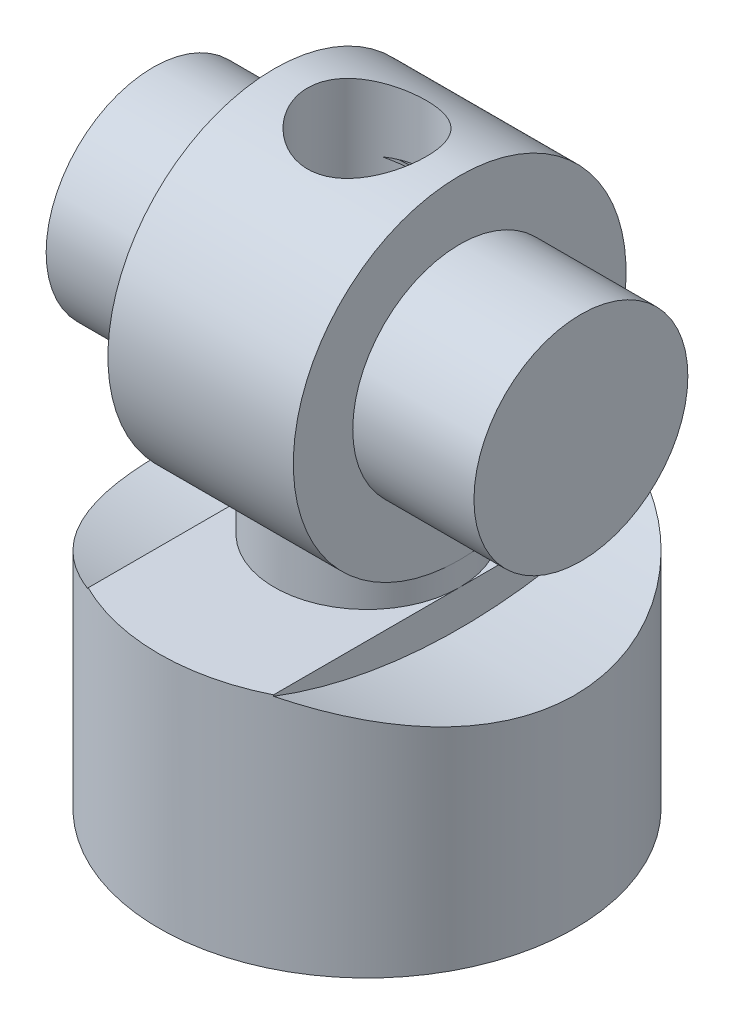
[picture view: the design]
ISO-10303-21;
HEADER;
FILE_DESCRIPTION(('STEP AP214'),'2;1');
FILE_NAME('part.step','',(''),(''),'','','');
FILE_SCHEMA(('AUTOMOTIVE_DESIGN { 1 0 10303 214 1 1 1 1 }'));
ENDSEC;
DATA;
#1=APPLICATION_CONTEXT('core data for automotive mechanical design processes');
#2=APPLICATION_PROTOCOL_DEFINITION('international standard','automotive_design',2000,#1);
#3=PRODUCT_CONTEXT('',#1,'mechanical');
#4=PRODUCT('Part','Part','',(#3));
#5=PRODUCT_RELATED_PRODUCT_CATEGORY('part','',(#4));
#6=PRODUCT_DEFINITION_FORMATION('','',#4);
#7=PRODUCT_DEFINITION_CONTEXT('part definition',#1,'design');
#8=PRODUCT_DEFINITION('design','',#6,#7);
#9=PRODUCT_DEFINITION_SHAPE('','',#8);
#10=(LENGTH_UNIT() NAMED_UNIT(*) SI_UNIT(.MILLI.,.METRE.));
#11=(NAMED_UNIT(*) PLANE_ANGLE_UNIT() SI_UNIT($,.RADIAN.));
#12=(NAMED_UNIT(*) SI_UNIT($,.STERADIAN.) SOLID_ANGLE_UNIT());
#13=UNCERTAINTY_MEASURE_WITH_UNIT(LENGTH_MEASURE(1.E-05),#10,'distance_accuracy_value','');
#14=(GEOMETRIC_REPRESENTATION_CONTEXT(3) GLOBAL_UNCERTAINTY_ASSIGNED_CONTEXT((#13)) GLOBAL_UNIT_ASSIGNED_CONTEXT((#10,
#11,#12)) REPRESENTATION_CONTEXT('',''));
#15=CARTESIAN_POINT('',(0.,0.,0.));
#16=DIRECTION('',(0.,0.,1.));
#17=DIRECTION('',(1.,0.,0.));
#18=AXIS2_PLACEMENT_3D('',#15,#16,#17);
#19=CARTESIAN_POINT('',(3.9,0.,0.));
#20=DIRECTION('',(1.,0.,0.));
#21=DIRECTION('',(0.,0.,-1.));
#22=AXIS2_PLACEMENT_3D('',#19,#20,#21);
#23=CYLINDRICAL_SURFACE('',#22,7.);
#24=CARTESIAN_POINT('',(-3.9,-7.,0.));
#25=CARTESIAN_POINT('',(-3.90000031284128,-7.0000002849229,0.101146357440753));
#26=CARTESIAN_POINT('',(-3.89606076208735,-6.99780299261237,0.202288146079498));
#27=CARTESIAN_POINT('',(-3.8803553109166,-6.98907110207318,0.4038084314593));
#28=CARTESIAN_POINT('',(-3.86858664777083,-6.98253497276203,0.504186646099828));
#29=CARTESIAN_POINT('',(-3.83737541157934,-6.96529106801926,0.70335165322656));
#30=CARTESIAN_POINT('',(-3.81793498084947,-6.95458445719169,0.802138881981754));
#31=CARTESIAN_POINT('',(-3.77162646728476,-6.92927102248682,0.997460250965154));
#32=CARTESIAN_POINT('',(-3.74475533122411,-6.91466259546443,1.09399344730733));
#33=CARTESIAN_POINT('',(-3.65367488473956,-6.8656158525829,1.37844239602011));
#34=CARTESIAN_POINT('',(-3.57884423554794,-6.82586770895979,1.56217036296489));
#35=CARTESIAN_POINT('',(-3.40371798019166,-6.73570207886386,1.91400928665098));
#36=CARTESIAN_POINT('',(-3.30341621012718,-6.68528201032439,2.08211644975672));
#37=CARTESIAN_POINT('',(-3.07231715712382,-6.57405157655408,2.41123481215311));
#38=CARTESIAN_POINT('',(-2.93988015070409,-6.51276165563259,2.57093203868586));
#39=CARTESIAN_POINT('',(-2.65187991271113,-6.38792749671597,2.86710248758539));
#40=CARTESIAN_POINT('',(-2.4962931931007,-6.32438101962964,3.00355181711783));
#41=CARTESIAN_POINT('',(-2.14756313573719,-6.19461051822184,3.26342871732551));
#42=CARTESIAN_POINT('',(-1.9522073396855,-6.12877524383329,3.38410558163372));
#43=CARTESIAN_POINT('',(-1.54017690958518,-6.01028349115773,3.59036592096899));
#44=CARTESIAN_POINT('',(-1.32353352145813,-5.95760808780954,3.67599990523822));
#45=CARTESIAN_POINT('',(-0.922013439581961,-5.88301311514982,3.79393677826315));
#46=CARTESIAN_POINT('',(-0.740093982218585,-5.85694711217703,3.83368428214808));
#47=CARTESIAN_POINT('',(-0.370897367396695,-5.82184998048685,3.88678839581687));
#48=CARTESIAN_POINT('',(-0.183625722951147,-5.81280192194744,3.9001712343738));
#49=CARTESIAN_POINT('',(0.191083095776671,-5.81303377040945,3.89982520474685));
#50=CARTESIAN_POINT('',(0.37852022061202,-5.8223342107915,3.8860659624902));
#51=CARTESIAN_POINT('',(0.747931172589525,-5.85794372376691,3.83216617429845));
#52=CARTESIAN_POINT('',(0.92990134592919,-5.88426391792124,3.79200837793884));
#53=CARTESIAN_POINT('',(1.28390008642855,-5.95046957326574,3.68723511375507));
#54=CARTESIAN_POINT('',(1.45593022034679,-5.99035288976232,3.62262351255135));
#55=CARTESIAN_POINT('',(1.78727171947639,-6.07937613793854,3.47115130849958));
#56=CARTESIAN_POINT('',(1.94657809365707,-6.12851967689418,3.3842820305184));
#57=CARTESIAN_POINT('',(2.2737904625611,-6.23962592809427,3.17538598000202));
#58=CARTESIAN_POINT('',(2.43929114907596,-6.30240002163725,3.05001538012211));
#59=CARTESIAN_POINT('',(2.74839589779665,-6.4283539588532,2.77475098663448));
#60=CARTESIAN_POINT('',(2.89198236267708,-6.49153408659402,2.62483768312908));
#61=CARTESIAN_POINT('',(3.16801707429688,-6.61889865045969,2.28605157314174));
#62=CARTESIAN_POINT('',(3.29781181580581,-6.68252127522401,2.09475977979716));
#63=CARTESIAN_POINT('',(3.46646074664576,-6.76786771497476,1.79084562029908));
#64=CARTESIAN_POINT('',(3.51835131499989,-6.79464354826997,1.68666859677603));
#65=CARTESIAN_POINT('',(3.612893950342,-6.84407556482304,1.47329042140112));
#66=CARTESIAN_POINT('',(3.65555155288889,-6.8667342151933,1.36409232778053));
#67=CARTESIAN_POINT('',(3.72840544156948,-6.90580423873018,1.14932095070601));
#68=CARTESIAN_POINT('',(3.75926673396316,-6.92254271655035,1.04403213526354));
#69=CARTESIAN_POINT('',(3.81209300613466,-6.95137123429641,0.830670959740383));
#70=CARTESIAN_POINT('',(3.83406268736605,-6.96346373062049,0.722600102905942));
#71=CARTESIAN_POINT('',(3.868792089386,-6.9826458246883,0.504603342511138));
#72=CARTESIAN_POINT('',(3.88155641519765,-6.9897379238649,0.394678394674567));
#73=CARTESIAN_POINT('',(3.89769038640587,-6.99871019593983,0.173933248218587));
#74=CARTESIAN_POINT('',(3.90106096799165,-7.00059088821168,0.0631131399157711));
#75=CARTESIAN_POINT('',(3.89851220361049,-6.9991712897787,-0.145684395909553));
#76=CARTESIAN_POINT('',(3.8936119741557,-6.99643934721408,-0.243680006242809));
#77=CARTESIAN_POINT('',(3.87646786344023,-6.98691292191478,-0.438858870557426));
#78=CARTESIAN_POINT('',(3.86422167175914,-6.98011716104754,-0.536041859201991));
#79=CARTESIAN_POINT('',(3.8325365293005,-6.96262599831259,-0.728834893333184));
#80=CARTESIAN_POINT('',(3.81310029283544,-6.95193206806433,-0.824445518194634));
#81=CARTESIAN_POINT('',(3.7672642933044,-6.92689811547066,-1.01350789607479));
#82=CARTESIAN_POINT('',(3.7408618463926,-6.91255668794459,-1.10695880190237));
#83=CARTESIAN_POINT('',(3.65188020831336,-6.86467000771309,-1.38231185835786));
#84=CARTESIAN_POINT('',(3.5793522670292,-6.82616282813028,-1.56025439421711));
#85=CARTESIAN_POINT('',(3.41035528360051,-6.73908732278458,-1.90153537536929));
#86=CARTESIAN_POINT('',(3.31387989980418,-6.69051633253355,-2.06486993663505));
#87=CARTESIAN_POINT('',(3.0884274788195,-6.58161394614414,-2.39055758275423));
#88=CARTESIAN_POINT('',(2.95712331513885,-6.52058610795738,-2.5510686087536));
#89=CARTESIAN_POINT('',(2.67130243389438,-6.39603792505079,-2.8490076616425));
#90=CARTESIAN_POINT('',(2.51676008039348,-6.33251488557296,-2.98640983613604));
#91=CARTESIAN_POINT('',(2.17019140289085,-6.20252665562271,-3.24840604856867));
#92=CARTESIAN_POINT('',(1.97595074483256,-6.13642030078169,-3.37027211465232));
#93=CARTESIAN_POINT('',(1.5660225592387,-6.0169979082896,-3.57914696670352));
#94=CARTESIAN_POINT('',(1.35036576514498,-5.96366390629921,-3.66620482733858));
#95=CARTESIAN_POINT('',(0.949863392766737,-5.88745193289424,-3.78707116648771));
#96=CARTESIAN_POINT('',(0.767997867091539,-5.86053840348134,-3.82820584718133));
#97=CARTESIAN_POINT('',(0.398636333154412,-5.82368322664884,-3.88405483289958));
#98=CARTESIAN_POINT('',(0.211146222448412,-5.81372439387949,-3.89879589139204));
#99=CARTESIAN_POINT('',(-0.16431738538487,-5.81220321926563,-3.90106353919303));
#100=CARTESIAN_POINT('',(-0.352291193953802,-5.82066508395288,-3.88855431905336));
#101=CARTESIAN_POINT('',(-0.722985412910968,-5.85478864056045,-3.83697351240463));
#102=CARTESIAN_POINT('',(-0.905702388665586,-5.88046132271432,-3.79788495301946));
#103=CARTESIAN_POINT('',(-1.26056326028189,-5.94547234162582,-3.69526481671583));
#104=CARTESIAN_POINT('',(-1.43274964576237,-5.98475081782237,-3.63184018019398));
#105=CARTESIAN_POINT('',(-1.76456240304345,-6.07272836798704,-3.48273610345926));
#106=CARTESIAN_POINT('',(-1.92418392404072,-6.12143105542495,-3.39704812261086));
#107=CARTESIAN_POINT('',(-2.25197054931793,-6.23169761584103,-3.1908552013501));
#108=CARTESIAN_POINT('',(-2.41778139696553,-6.29409283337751,-3.06704558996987));
#109=CARTESIAN_POINT('',(-2.72777488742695,-6.41955139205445,-2.79497203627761));
#110=CARTESIAN_POINT('',(-2.87193982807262,-6.48261523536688,-2.64668828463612));
#111=CARTESIAN_POINT('',(-3.14998913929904,-6.61026335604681,-2.31081364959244));
#112=CARTESIAN_POINT('',(-3.28116085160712,-6.67429932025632,-2.12072173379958));
#113=CARTESIAN_POINT('',(-3.45204991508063,-6.76049282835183,-1.81846116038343));
#114=CARTESIAN_POINT('',(-3.50471596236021,-6.787588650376,-1.71481303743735));
#115=CARTESIAN_POINT('',(-3.60086999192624,-6.83773159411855,-1.5024293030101));
#116=CARTESIAN_POINT('',(-3.64436349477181,-6.86078114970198,-1.39369680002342));
#117=CARTESIAN_POINT('',(-3.71848344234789,-6.90045090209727,-1.18090483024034));
#118=CARTESIAN_POINT('',(-3.74986495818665,-6.91743981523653,-1.07717625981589));
#119=CARTESIAN_POINT('',(-3.80397740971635,-6.94692221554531,-0.866908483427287));
#120=CARTESIAN_POINT('',(-3.8267128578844,-6.95941804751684,-0.760370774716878));
#121=CARTESIAN_POINT('',(-3.86321922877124,-6.97955808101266,-0.545364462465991));
#122=CARTESIAN_POINT('',(-3.87699416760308,-6.98720445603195,-0.436896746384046));
#123=CARTESIAN_POINT('',(-3.89538409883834,-6.99742510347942,-0.218950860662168));
#124=CARTESIAN_POINT('',(-3.89999966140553,-6.99999969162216,-0.109472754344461));
#125=CARTESIAN_POINT('',(-3.9,-7.,0.));
#126=B_SPLINE_CURVE_WITH_KNOTS('',3,(#24,#25,#26,#27,#28,#29,#30,#31,#32,#33,#34,#35,#36,#37,
#38,#39,#40,#41,#42,#43,#44,#45,#46,#47,#48,#49,#50,#51,#52,#53,#54,#55,#56,#57,#58,#59,#60,#61,
#62,#63,#64,#65,#66,#67,#68,#69,#70,#71,#72,#73,#74,#75,#76,#77,#78,#79,#80,#81,#82,#83,#84,#85,
#86,#87,#88,#89,#90,#91,#92,#93,#94,#95,#96,#97,#98,#99,#100,#101,#102,#103,#104,#105,#106,#107,
#108,#109,#110,#111,#112,#113,#114,#115,#116,#117,#118,#119,#120,#121,#122,#123,#124,#125),
.UNSPECIFIED.,.T.,.F.,(4,2,2,2,2,2,2,2,2,2,2,2,2,2,2,2,2,2,2,2,2,2,2,2,2,2,2,2,2,2,2,2,2,2,2,2,
2,2,2,2,2,2,2,2,2,2,2,2,2,2,4),(0.,0.303330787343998,0.606768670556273,0.910121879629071,
1.21359992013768,1.81765602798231,2.42185845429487,3.06822728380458,3.71525645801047,
4.42832801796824,5.14036813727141,5.70199096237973,6.26305477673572,6.82474682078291,
7.38680627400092,7.94877689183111,8.51096687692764,9.15905767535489,9.80766618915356,
10.5228095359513,10.8806537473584,11.2382828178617,11.5707819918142,11.903105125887,
12.2352618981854,12.5673855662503,12.8614963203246,13.1556996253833,13.4497919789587,
13.7439978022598,14.3292696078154,14.9146965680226,15.5605601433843,16.2071415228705,
16.9195476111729,17.6309457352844,18.1936677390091,18.7558190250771,19.3187094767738,
19.8819597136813,20.4427626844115,21.0037811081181,21.6495812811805,22.2959067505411,
23.0107914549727,23.3684940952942,23.7259808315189,24.0546214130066,24.383090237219,
24.7114117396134,25.0397128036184),.UNSPECIFIED.);
#127=CARTESIAN_POINT('',(3.9,-7.,0.));
#128=VERTEX_POINT('',#127);
#129=CARTESIAN_POINT('',(-3.9,-7.,0.));
#130=VERTEX_POINT('',#129);
#131=EDGE_CURVE('E174',#128,#130,#126,.T.);
#132=ORIENTED_EDGE('',*,*,#131,.T.);
#133=CARTESIAN_POINT('',(-3.9,0.,0.));
#134=DIRECTION('',(1.,0.,0.));
#135=DIRECTION('',(0.,0.,-1.));
#136=AXIS2_PLACEMENT_3D('',#133,#134,#135);
#137=CIRCLE('',#136,7.);
#138=EDGE_CURVE('E290',#130,#130,#137,.T.);
#139=ORIENTED_EDGE('',*,*,#138,.T.);
#140=EDGE_CURVE('E299',#130,#128,#126,.T.);
#141=ORIENTED_EDGE('',*,*,#140,.T.);
#142=CARTESIAN_POINT('',(3.9,0.,0.));
#143=DIRECTION('',(1.,0.,0.));
#144=DIRECTION('',(0.,0.,-1.));
#145=AXIS2_PLACEMENT_3D('',#142,#143,#144);
#146=CIRCLE('',#145,7.);
#147=EDGE_CURVE('E293',#128,#128,#146,.T.);
#148=ORIENTED_EDGE('',*,*,#147,.F.);
#149=EDGE_LOOP('',(#132,#139,#141,#148));
#150=FACE_BOUND('',#149,.T.);
#151=CARTESIAN_POINT('',(-2.5,7.,0.));
#152=CARTESIAN_POINT('',(-2.49999223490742,6.99999423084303,-0.13564073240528));
#153=CARTESIAN_POINT('',(-2.48890866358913,6.99601508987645,-0.271414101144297));
#154=CARTESIAN_POINT('',(-2.44496507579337,6.98050486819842,-0.539073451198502));
#155=CARTESIAN_POINT('',(-2.41207047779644,6.96896179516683,-0.67095291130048));
#156=CARTESIAN_POINT('',(-2.32580712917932,6.93957817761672,-0.926706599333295));
#157=CARTESIAN_POINT('',(-2.27248899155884,6.92175320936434,-1.05059973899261));
#158=CARTESIAN_POINT('',(-2.14708821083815,6.88160372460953,-1.28763407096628));
#159=CARTESIAN_POINT('',(-2.07500711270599,6.85927957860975,-1.40077614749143));
#160=CARTESIAN_POINT('',(-1.91115888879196,6.81147433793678,-1.61758480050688));
#161=CARTESIAN_POINT('',(-1.81878583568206,6.78590953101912,-1.72077491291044));
#162=CARTESIAN_POINT('',(-1.6182590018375,6.73493649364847,-1.91057783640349));
#163=CARTESIAN_POINT('',(-1.51010025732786,6.70952831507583,-1.99718541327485));
#164=CARTESIAN_POINT('',(-1.276602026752,6.66080066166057,-2.15423743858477));
#165=CARTESIAN_POINT('',(-1.15080488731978,6.63758100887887,-2.22403549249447));
#166=CARTESIAN_POINT('',(-0.888295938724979,6.59714347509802,-2.34127586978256));
#167=CARTESIAN_POINT('',(-0.751588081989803,6.57992343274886,-2.3887262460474));
#168=CARTESIAN_POINT('',(-0.476577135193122,6.55432037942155,-2.45809130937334));
#169=CARTESIAN_POINT('',(-0.338530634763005,6.54562733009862,-2.4809052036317));
#170=CARTESIAN_POINT('',(-0.0603163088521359,6.53715061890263,-2.50316152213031));
#171=CARTESIAN_POINT('',(0.0798507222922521,6.53736369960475,-2.50261249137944));
#172=CARTESIAN_POINT('',(0.350355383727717,6.54640587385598,-2.47885081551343));
#173=CARTESIAN_POINT('',(0.480817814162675,6.55477360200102,-2.45685171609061));
#174=CARTESIAN_POINT('',(0.736061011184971,6.57842075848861,-2.39280867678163));
#175=CARTESIAN_POINT('',(0.860840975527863,6.59370115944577,-2.35076191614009));
#176=CARTESIAN_POINT('',(1.10377675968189,6.62975215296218,-2.24709441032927));
#177=CARTESIAN_POINT('',(1.22177540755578,6.65061550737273,-2.18513901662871));
#178=CARTESIAN_POINT('',(1.44606164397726,6.69544587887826,-2.04364869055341));
#179=CARTESIAN_POINT('',(1.55234602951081,6.71941374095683,-1.96410896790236));
#180=CARTESIAN_POINT('',(1.75694257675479,6.7695208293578,-1.7840468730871));
#181=CARTESIAN_POINT('',(1.85438627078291,6.79570379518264,-1.68254775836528));
#182=CARTESIAN_POINT('',(2.03114616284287,6.84604690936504,-1.46429791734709));
#183=CARTESIAN_POINT('',(2.11045421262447,6.87020614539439,-1.34754037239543));
#184=CARTESIAN_POINT('',(2.24953773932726,6.91418824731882,-1.10000408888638));
#185=CARTESIAN_POINT('',(2.30903444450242,6.93394802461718,-0.969057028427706));
#186=CARTESIAN_POINT('',(2.40477778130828,6.96641261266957,-0.698268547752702));
#187=CARTESIAN_POINT('',(2.44107169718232,6.97913176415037,-0.558445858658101));
#188=CARTESIAN_POINT('',(2.47668095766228,6.99169887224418,-0.347747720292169));
#189=CARTESIAN_POINT('',(2.48541369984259,6.99480177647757,-0.278535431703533));
#190=CARTESIAN_POINT('',(2.49707521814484,6.99895382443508,-0.139560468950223));
#191=CARTESIAN_POINT('',(2.50000399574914,7.00000296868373,-0.0697977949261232));
#192=CARTESIAN_POINT('',(2.49999223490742,6.99999423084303,0.135640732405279));
#193=CARTESIAN_POINT('',(2.48890866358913,6.99601508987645,0.271414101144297));
#194=CARTESIAN_POINT('',(2.44496507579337,6.98050486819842,0.539073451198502));
#195=CARTESIAN_POINT('',(2.41207047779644,6.96896179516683,0.67095291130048));
#196=CARTESIAN_POINT('',(2.32580712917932,6.93957817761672,0.926706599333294));
#197=CARTESIAN_POINT('',(2.27248899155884,6.92175320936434,1.05059973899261));
#198=CARTESIAN_POINT('',(2.14708821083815,6.88160372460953,1.28763407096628));
#199=CARTESIAN_POINT('',(2.07500711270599,6.85927957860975,1.40077614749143));
#200=CARTESIAN_POINT('',(1.91115888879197,6.81147433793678,1.61758480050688));
#201=CARTESIAN_POINT('',(1.81878583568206,6.78590953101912,1.72077491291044));
#202=CARTESIAN_POINT('',(1.6182590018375,6.73493649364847,1.91057783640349));
#203=CARTESIAN_POINT('',(1.51010025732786,6.70952831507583,1.99718541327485));
#204=CARTESIAN_POINT('',(1.276602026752,6.66080066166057,2.15423743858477));
#205=CARTESIAN_POINT('',(1.15080488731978,6.63758100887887,2.22403549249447));
#206=CARTESIAN_POINT('',(0.88829593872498,6.59714347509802,2.34127586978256));
#207=CARTESIAN_POINT('',(0.751588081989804,6.57992343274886,2.3887262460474));
#208=CARTESIAN_POINT('',(0.476577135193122,6.55432037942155,2.45809130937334));
#209=CARTESIAN_POINT('',(0.338530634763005,6.54562733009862,2.4809052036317));
#210=CARTESIAN_POINT('',(0.060316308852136,6.53715061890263,2.50316152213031));
#211=CARTESIAN_POINT('',(-0.0798507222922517,6.53736369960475,2.50261249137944));
#212=CARTESIAN_POINT('',(-0.350355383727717,6.54640587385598,2.47885081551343));
#213=CARTESIAN_POINT('',(-0.480817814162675,6.55477360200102,2.45685171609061));
#214=CARTESIAN_POINT('',(-0.736061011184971,6.57842075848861,2.39280867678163));
#215=CARTESIAN_POINT('',(-0.860840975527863,6.59370115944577,2.35076191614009));
#216=CARTESIAN_POINT('',(-1.10377675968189,6.62975215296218,2.24709441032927));
#217=CARTESIAN_POINT('',(-1.22177540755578,6.65061550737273,2.18513901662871));
#218=CARTESIAN_POINT('',(-1.44606164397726,6.69544587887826,2.04364869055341));
#219=CARTESIAN_POINT('',(-1.55234602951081,6.71941374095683,1.96410896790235));
#220=CARTESIAN_POINT('',(-1.75694257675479,6.7695208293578,1.7840468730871));
#221=CARTESIAN_POINT('',(-1.85438627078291,6.79570379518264,1.68254775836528));
#222=CARTESIAN_POINT('',(-2.03114616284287,6.84604690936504,1.46429791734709));
#223=CARTESIAN_POINT('',(-2.11045421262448,6.87020614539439,1.34754037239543));
#224=CARTESIAN_POINT('',(-2.24953773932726,6.91418824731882,1.10000408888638));
#225=CARTESIAN_POINT('',(-2.30903444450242,6.93394802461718,0.969057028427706));
#226=CARTESIAN_POINT('',(-2.40477778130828,6.96641261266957,0.698268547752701));
#227=CARTESIAN_POINT('',(-2.44107169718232,6.97913176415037,0.5584458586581));
#228=CARTESIAN_POINT('',(-2.47668095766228,6.99169887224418,0.347747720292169));
#229=CARTESIAN_POINT('',(-2.48541369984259,6.99480177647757,0.278535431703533));
#230=CARTESIAN_POINT('',(-2.49707521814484,6.99895382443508,0.139560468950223));
#231=CARTESIAN_POINT('',(-2.50000399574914,7.00000296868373,0.0697977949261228));
#232=CARTESIAN_POINT('',(-2.5,7.,0.));
#233=B_SPLINE_CURVE_WITH_KNOTS('',3,(#151,#152,#153,#154,#155,#156,#157,#158,#159,#160,#161,
#162,#163,#164,#165,#166,#167,#168,#169,#170,#171,#172,#173,#174,#175,#176,#177,#178,#179,#180,
#181,#182,#183,#184,#185,#186,#187,#188,#189,#190,#191,#192,#193,#194,#195,#196,#197,#198,#199,
#200,#201,#202,#203,#204,#205,#206,#207,#208,#209,#210,#211,#212,#213,#214,#215,#216,#217,#218,
#219,#220,#221,#222,#223,#224,#225,#226,#227,#228,#229,#230,#231,#232),.UNSPECIFIED.,.T.,.F.,(4,
2,2,2,2,2,2,2,2,2,2,2,2,2,2,2,2,2,2,2,2,2,2,2,2,2,2,2,2,2,2,2,2,2,2,2,2,2,2,2,4),(0.,
0.406652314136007,0.8139509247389,1.22024664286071,1.62650891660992,2.0471353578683,
2.46789435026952,2.90289671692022,3.3377422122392,3.75611572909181,4.17433622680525,
4.57019166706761,4.96610282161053,5.36905142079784,5.77210992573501,6.1994977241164,
6.62707716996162,7.06044132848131,7.4929195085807,7.70217407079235,7.91142857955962,
8.31808089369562,8.72537950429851,9.13167522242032,9.53793749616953,9.95856393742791,
10.3793229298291,10.8143252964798,11.2491707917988,11.6675443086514,12.0857648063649,
12.4816202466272,12.8775314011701,13.2804800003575,13.6835385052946,14.110926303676,
14.5385057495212,14.9718699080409,15.4043480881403,15.613602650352,15.8228571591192),.UNSPECIFIED.);
#234=CARTESIAN_POINT('',(-2.5,7.,0.));
#235=VERTEX_POINT('',#234);
#236=EDGE_CURVE('E180',#235,#235,#233,.T.);
#237=ORIENTED_EDGE('',*,*,#236,.T.);
#238=EDGE_LOOP('',(#237));
#239=FACE_BOUND('',#238,.T.);
#240=ADVANCED_FACE('F14',(#150,#239),#23,.T.);
#241=CARTESIAN_POINT('',(9.,0.,0.));
#242=DIRECTION('',(-1.,0.,0.));
#243=DIRECTION('',(0.,0.,1.));
#244=AXIS2_PLACEMENT_3D('',#241,#242,#243);
#245=CYLINDRICAL_SURFACE('',#244,4.5);
#246=CARTESIAN_POINT('',(0.,-3.74165738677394,2.5));
#247=CARTESIAN_POINT('',(0.127867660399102,-3.7416726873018,2.4999886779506));
#248=CARTESIAN_POINT('',(0.255847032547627,-3.74831704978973,2.49012046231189));
#249=CARTESIAN_POINT('',(0.507679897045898,-3.77384839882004,2.45123834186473));
#250=CARTESIAN_POINT('',(0.631526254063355,-3.79275551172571,2.42219296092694));
#251=CARTESIAN_POINT('',(0.870945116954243,-3.83989933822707,2.34672518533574));
#252=CARTESIAN_POINT('',(0.986564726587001,-3.86807667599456,2.30041313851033));
#253=CARTESIAN_POINT('',(1.20834600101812,-3.93048941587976,2.19206578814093));
#254=CARTESIAN_POINT('',(1.31450555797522,-3.96472616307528,2.13002699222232));
#255=CARTESIAN_POINT('',(1.52641671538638,-4.03969403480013,1.98449846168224));
#256=CARTESIAN_POINT('',(1.63099357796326,-4.08073069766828,1.89945493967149));
#257=CARTESIAN_POINT('',(1.82534633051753,-4.16222299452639,1.71353751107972));
#258=CARTESIAN_POINT('',(1.91511315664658,-4.20267825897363,1.61265398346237));
#259=CARTESIAN_POINT('',(2.08508983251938,-4.28269640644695,1.3870985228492));
#260=CARTESIAN_POINT('',(2.1637603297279,-4.32186646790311,1.26111369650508));
#261=CARTESIAN_POINT('',(2.29824166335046,-4.39073714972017,0.995108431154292));
#262=CARTESIAN_POINT('',(2.35407027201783,-4.4204451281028,0.85509901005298));
#263=CARTESIAN_POINT('',(2.43630568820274,-4.46480622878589,0.577542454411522));
#264=CARTESIAN_POINT('',(2.46480060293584,-4.48051966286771,0.440787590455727));
#265=CARTESIAN_POINT('',(2.49853448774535,-4.49916269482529,0.163616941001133));
#266=CARTESIAN_POINT('',(2.50379152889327,-4.50210222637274,0.0232040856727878));
#267=CARTESIAN_POINT('',(2.4914765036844,-4.4952695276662,-0.241178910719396));
#268=CARTESIAN_POINT('',(2.47628215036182,-4.48682112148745,-0.365303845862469));
#269=CARTESIAN_POINT('',(2.42789099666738,-4.46029652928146,-0.608906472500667));
#270=CARTESIAN_POINT('',(2.39469280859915,-4.44221960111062,-0.72838380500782));
#271=CARTESIAN_POINT('',(2.31126649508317,-4.39780601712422,-0.960979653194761));
#272=CARTESIAN_POINT('',(2.26086630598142,-4.37138611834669,-1.07401990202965));
#273=CARTESIAN_POINT('',(2.14483738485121,-4.31251997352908,-1.29025059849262));
#274=CARTESIAN_POINT('',(2.07920386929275,-4.28007183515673,-1.39343793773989));
#275=CARTESIAN_POINT('',(1.92640653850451,-4.20785286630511,-1.59909620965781));
#276=CARTESIAN_POINT('',(1.83767397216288,-4.16766932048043,-1.70025747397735));
#277=CARTESIAN_POINT('',(1.64533173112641,-4.08650106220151,-1.88703556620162));
#278=CARTESIAN_POINT('',(1.54170632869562,-4.04551554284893,-1.97263574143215));
#279=CARTESIAN_POINT('',(1.31107929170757,-3.96312397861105,-2.13367090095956));
#280=CARTESIAN_POINT('',(1.1828097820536,-3.92201714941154,-2.2074790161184));
#281=CARTESIAN_POINT('',(0.980669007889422,-3.86749177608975,-2.30082855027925));
#282=CARTESIAN_POINT('',(0.911652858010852,-3.8505034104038,-2.32905476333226));
#283=CARTESIAN_POINT('',(0.770776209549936,-3.81960529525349,-2.3793879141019));
#284=CARTESIAN_POINT('',(0.698917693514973,-3.80569344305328,-2.4014990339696));
#285=CARTESIAN_POINT('',(0.558744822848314,-3.7825660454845,-2.43774893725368));
#286=CARTESIAN_POINT('',(0.49060568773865,-3.77306418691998,-2.45238335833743));
#287=CARTESIAN_POINT('',(0.352979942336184,-3.75764870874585,-2.47593920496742));
#288=CARTESIAN_POINT('',(0.283494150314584,-3.75173297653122,-2.48486399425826));
#289=CARTESIAN_POINT('',(0.143844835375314,-3.7437735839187,-2.49684067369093));
#290=CARTESIAN_POINT('',(0.0736818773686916,-3.74172693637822,-2.49989709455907));
#291=CARTESIAN_POINT('',(-0.0666321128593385,-3.74159115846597,-2.5000979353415));
#292=CARTESIAN_POINT('',(-0.136783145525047,-3.74350157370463,-2.49724303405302));
#293=CARTESIAN_POINT('',(-0.32521266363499,-3.75390669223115,-2.48160454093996));
#294=CARTESIAN_POINT('',(-0.442885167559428,-3.7660681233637,-2.46327912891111));
#295=CARTESIAN_POINT('',(-0.673061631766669,-3.79999671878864,-2.41059641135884));
#296=CARTESIAN_POINT('',(-0.785563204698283,-3.8217682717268,-2.37623178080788));
#297=CARTESIAN_POINT('',(-1.00774180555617,-3.8734200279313,-2.29111009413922));
#298=CARTESIAN_POINT('',(-1.11711092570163,-3.90359765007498,-2.23973536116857));
#299=CARTESIAN_POINT('',(-1.32632576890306,-3.96852930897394,-2.12255957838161));
#300=CARTESIAN_POINT('',(-1.42616680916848,-4.00328557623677,-2.05675148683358));
#301=CARTESIAN_POINT('',(-1.63049062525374,-4.08021308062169,-1.90016864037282));
#302=CARTESIAN_POINT('',(-1.73309682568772,-4.12267224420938,-1.80707526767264));
#303=CARTESIAN_POINT('',(-1.92199935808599,-4.20557655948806,-1.60470900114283));
#304=CARTESIAN_POINT('',(-2.00828561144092,-4.24602045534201,-1.49542618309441));
#305=CARTESIAN_POINT('',(-2.16643294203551,-4.32300875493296,-1.25626042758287));
#306=CARTESIAN_POINT('',(-2.23726807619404,-4.3592262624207,-1.12558547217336));
#307=CARTESIAN_POINT('',(-2.35519631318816,-4.42090637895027,-0.851602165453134));
#308=CARTESIAN_POINT('',(-2.40231447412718,-4.44638033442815,-0.708307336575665));
#309=CARTESIAN_POINT('',(-2.46664777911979,-4.48148519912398,-0.428990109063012));
#310=CARTESIAN_POINT('',(-2.48643742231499,-4.49247473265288,-0.29373267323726));
#311=CARTESIAN_POINT('',(-2.50362240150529,-4.5020067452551,-0.0213910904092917));
#312=CARTESIAN_POINT('',(-2.50103007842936,-4.50055608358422,0.115692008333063));
#313=CARTESIAN_POINT('',(-2.47491437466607,-4.4861017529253,0.374337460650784));
#314=CARTESIAN_POINT('',(-2.45334235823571,-4.47417531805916,0.49616574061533));
#315=CARTESIAN_POINT('',(-2.39292228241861,-4.44133257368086,0.734167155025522));
#316=CARTESIAN_POINT('',(-2.3540722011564,-4.42041521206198,0.8503396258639));
#317=CARTESIAN_POINT('',(-2.25905612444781,-4.3705432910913,1.07814775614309));
#318=CARTESIAN_POINT('',(-2.202363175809,-4.34134725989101,1.18950897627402));
#319=CARTESIAN_POINT('',(-2.07393542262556,-4.27762772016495,1.40148896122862));
#320=CARTESIAN_POINT('',(-2.00219469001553,-4.24310211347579,1.50210346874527));
#321=CARTESIAN_POINT('',(-1.83613517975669,-4.16717195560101,1.70217916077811));
#322=CARTESIAN_POINT('',(-1.74016022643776,-4.12543450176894,1.8001424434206));
#323=CARTESIAN_POINT('',(-1.53330418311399,-4.04252541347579,1.97933250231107));
#324=CARTESIAN_POINT('',(-1.42240466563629,-4.0013545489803,2.06053826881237));
#325=CARTESIAN_POINT('',(-1.17899936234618,-3.92122408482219,2.20944802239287));
#326=CARTESIAN_POINT('',(-1.04552040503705,-3.88262653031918,2.27579178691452));
#327=CARTESIAN_POINT('',(-0.836526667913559,-3.83343009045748,2.35707752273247));
#328=CARTESIAN_POINT('',(-0.765460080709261,-3.81848976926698,2.38112244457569));
#329=CARTESIAN_POINT('',(-0.620861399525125,-3.79215325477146,2.4228459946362));
#330=CARTESIAN_POINT('',(-0.547330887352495,-3.78075483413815,2.44052862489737));
#331=CARTESIAN_POINT('',(-0.395409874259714,-3.7617084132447,2.4697920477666));
#332=CARTESIAN_POINT('',(-0.316943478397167,-3.75423236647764,2.48109451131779));
#333=CARTESIAN_POINT('',(-0.158999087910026,-3.74420222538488,2.49620181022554));
#334=CARTESIAN_POINT('',(-0.0795211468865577,-3.74164787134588,2.50000704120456));
#335=CARTESIAN_POINT('',(0.,-3.74165738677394,2.5));
#336=B_SPLINE_CURVE_WITH_KNOTS('',3,(#246,#247,#248,#249,#250,#251,#252,#253,#254,#255,#256,
#257,#258,#259,#260,#261,#262,#263,#264,#265,#266,#267,#268,#269,#270,#271,#272,#273,#274,#275,
#276,#277,#278,#279,#280,#281,#282,#283,#284,#285,#286,#287,#288,#289,#290,#291,#292,#293,#294,
#295,#296,#297,#298,#299,#300,#301,#302,#303,#304,#305,#306,#307,#308,#309,#310,#311,#312,#313,
#314,#315,#316,#317,#318,#319,#320,#321,#322,#323,#324,#325,#326,#327,#328,#329,#330,#331,#332,
#333,#334,#335),.UNSPECIFIED.,.T.,.F.,(4,2,2,2,2,2,2,2,2,2,2,2,2,2,2,2,2,2,2,2,2,2,2,2,2,2,2,2,
2,2,2,2,2,2,2,2,2,2,2,2,2,2,2,2,4),(0.,0.383275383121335,0.767181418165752,1.14867490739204,
1.53025318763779,1.95124472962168,2.37249297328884,2.8308639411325,3.2888775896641,
3.70817544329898,4.12714717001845,4.50138183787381,4.8756453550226,5.25376784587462,
5.63200923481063,6.05157027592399,6.47157769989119,6.92969119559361,7.15882945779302,
7.38781062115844,7.59850621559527,7.80907756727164,8.01948627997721,8.22987083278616,
8.58719279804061,8.94467811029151,9.31690871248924,9.68932132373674,10.122176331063,
10.5552977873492,11.0117233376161,11.4676656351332,11.8767730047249,12.2856548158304,
12.6568475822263,13.0280837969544,13.4115163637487,13.7951002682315,14.2233400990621,
14.6521136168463,15.1111969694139,15.3403711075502,15.5694008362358,15.80777312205,
16.0461328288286),.UNSPECIFIED.);
#337=CARTESIAN_POINT('',(0.,-3.74165738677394,2.5));
#338=VERTEX_POINT('',#337);
#339=EDGE_CURVE('E214',#338,#338,#336,.T.);
#340=ORIENTED_EDGE('',*,*,#339,.T.);
#341=EDGE_LOOP('',(#340));
#342=FACE_BOUND('',#341,.T.);
#343=CARTESIAN_POINT('',(0.,-3.30870065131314,-3.05));
#344=CARTESIAN_POINT('',(0.0740543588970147,-3.30870135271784,-3.04999955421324));
#345=CARTESIAN_POINT('',(0.148113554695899,-3.31120079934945,-3.04729547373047));
#346=CARTESIAN_POINT('',(0.29550128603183,-3.32105327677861,-3.03655247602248));
#347=CARTESIAN_POINT('',(0.368829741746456,-3.32840683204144,-3.02851298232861));
#348=CARTESIAN_POINT('',(0.586950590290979,-3.35728100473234,-2.99658701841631));
#349=CARTESIAN_POINT('',(0.729787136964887,-3.385614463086,-2.96489335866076));
#350=CARTESIAN_POINT('',(1.00481607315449,-3.45535402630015,-2.88328172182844));
#351=CARTESIAN_POINT('',(1.13710040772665,-3.49662694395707,-2.83354864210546));
#352=CARTESIAN_POINT('',(1.39123632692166,-3.58733287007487,-2.71780374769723));
#353=CARTESIAN_POINT('',(1.51308617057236,-3.6367672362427,-2.65178922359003));
#354=CARTESIAN_POINT('',(1.76446479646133,-3.74781440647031,-2.49293203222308));
#355=CARTESIAN_POINT('',(1.89204410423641,-3.81010328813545,-2.39747643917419));
#356=CARTESIAN_POINT('',(2.13108358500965,-3.93428541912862,-2.18776550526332));
#357=CARTESIAN_POINT('',(2.24252540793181,-3.99617814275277,-2.07348907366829));
#358=CARTESIAN_POINT('',(2.46301512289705,-4.1236708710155,-1.80832137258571));
#359=CARTESIAN_POINT('',(2.56913328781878,-4.18840811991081,-1.65450535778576));
#360=CARTESIAN_POINT('',(2.70696690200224,-4.27480018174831,-1.40843177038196));
#361=CARTESIAN_POINT('',(2.74934801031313,-4.30180769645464,-1.3238668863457));
#362=CARTESIAN_POINT('',(2.82644155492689,-4.35148238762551,-1.15011183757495));
#363=CARTESIAN_POINT('',(2.86115705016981,-4.37415129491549,-1.06092353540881));
#364=CARTESIAN_POINT('',(2.93723315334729,-4.42421178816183,-0.834029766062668));
#365=CARTESIAN_POINT('',(2.97356864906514,-4.44850916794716,-0.693888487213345));
#366=CARTESIAN_POINT('',(3.02602447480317,-4.48374237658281,-0.408328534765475));
#367=CARTESIAN_POINT('',(3.04216027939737,-4.49468843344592,-0.262913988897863));
#368=CARTESIAN_POINT('',(3.05336718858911,-4.5022807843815,0.0293654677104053));
#369=CARTESIAN_POINT('',(3.04840293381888,-4.49890307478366,0.176232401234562));
#370=CARTESIAN_POINT('',(3.01761506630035,-4.47809945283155,0.466749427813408));
#371=CARTESIAN_POINT('',(2.99178532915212,-4.46066941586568,0.610398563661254));
#372=CARTESIAN_POINT('',(2.92131598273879,-4.41371882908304,0.888013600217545));
#373=CARTESIAN_POINT('',(2.87702540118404,-4.38442289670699,1.02210773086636));
#374=CARTESIAN_POINT('',(2.77159197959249,-4.31597239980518,1.28074304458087));
#375=CARTESIAN_POINT('',(2.71044594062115,-4.27681596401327,1.40528240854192));
#376=CARTESIAN_POINT('',(2.56551457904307,-4.18638203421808,1.65649516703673));
#377=CARTESIAN_POINT('',(2.47995424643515,-4.13423576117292,1.78182668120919));
#378=CARTESIAN_POINT('',(2.29260341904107,-4.02464324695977,2.01721180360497));
#379=CARTESIAN_POINT('',(2.19079412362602,-3.96719089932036,2.12724743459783));
#380=CARTESIAN_POINT('',(1.95420691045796,-3.841187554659,2.34819750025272));
#381=CARTESIAN_POINT('',(1.81676442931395,-3.7723979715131,2.4561343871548));
#382=CARTESIAN_POINT('',(1.52359640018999,-3.64029455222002,2.64798057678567));
#383=CARTESIAN_POINT('',(1.36788117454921,-3.57697765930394,2.7319033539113));
#384=CARTESIAN_POINT('',(1.07873972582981,-3.4781328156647,2.85610629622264));
#385=CARTESIAN_POINT('',(0.948783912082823,-3.43957561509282,2.90201639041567));
#386=CARTESIAN_POINT('',(0.680934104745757,-3.37555318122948,2.97625031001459));
#387=CARTESIAN_POINT('',(0.54305511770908,-3.35006405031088,3.00460625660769));
#388=CARTESIAN_POINT('',(0.261369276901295,-3.31605166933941,3.04212029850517));
#389=CARTESIAN_POINT('',(0.117523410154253,-3.30766771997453,3.05112079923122));
#390=CARTESIAN_POINT('',(-0.169846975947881,-3.30994043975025,3.04865479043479));
#391=CARTESIAN_POINT('',(-0.313371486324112,-3.32059763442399,3.03718771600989));
#392=CARTESIAN_POINT('',(-0.579273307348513,-3.35672225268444,2.99716587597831));
#393=CARTESIAN_POINT('',(-0.702224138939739,-3.3804057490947,2.97065905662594));
#394=CARTESIAN_POINT('',(-0.941707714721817,-3.43813602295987,2.9036484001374));
#395=CARTESIAN_POINT('',(-1.05823445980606,-3.47219229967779,2.86313172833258));
#396=CARTESIAN_POINT('',(-1.33453129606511,-3.56435394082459,2.74826045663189));
#397=CARTESIAN_POINT('',(-1.49008084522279,-3.62637602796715,2.6668870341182));
#398=CARTESIAN_POINT('',(-1.78349065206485,-3.75646016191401,2.48031899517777));
#399=CARTESIAN_POINT('',(-1.9213174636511,-3.82453323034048,2.37508034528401));
#400=CARTESIAN_POINT('',(-2.17938375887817,-3.9604362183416,2.14091948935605));
#401=CARTESIAN_POINT('',(-2.29935531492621,-4.02824992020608,2.01169148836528));
#402=CARTESIAN_POINT('',(-2.51660188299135,-4.1560914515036,1.7321777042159));
#403=CARTESIAN_POINT('',(-2.61391283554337,-4.21613154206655,1.58192588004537));
#404=CARTESIAN_POINT('',(-2.7672445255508,-4.31303677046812,1.2910804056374));
#405=CARTESIAN_POINT('',(-2.82752395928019,-4.35212259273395,1.15347804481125));
#406=CARTESIAN_POINT('',(-2.92771339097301,-4.41786925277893,0.868215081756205));
#407=CARTESIAN_POINT('',(-2.96763645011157,-4.44453805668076,0.720560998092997));
#408=CARTESIAN_POINT('',(-3.02511265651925,-4.48311795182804,0.418279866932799));
#409=CARTESIAN_POINT('',(-3.04255880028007,-4.49495844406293,0.263623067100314));
#410=CARTESIAN_POINT('',(-3.05359112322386,-4.50243250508,-0.0469294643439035));
#411=CARTESIAN_POINT('',(-3.04718207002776,-4.49806931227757,-0.202824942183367));
#412=CARTESIAN_POINT('',(-3.01241336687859,-4.47459437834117,-0.498210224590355));
#413=CARTESIAN_POINT('',(-2.98584821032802,-4.45668871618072,-0.638015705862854));
#414=CARTESIAN_POINT('',(-2.91428327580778,-4.40906289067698,-0.910676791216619));
#415=CARTESIAN_POINT('',(-2.86928056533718,-4.37934084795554,-1.04353128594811));
#416=CARTESIAN_POINT('',(-2.75996758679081,-4.30849145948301,-1.30628099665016));
#417=CARTESIAN_POINT('',(-2.6947819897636,-4.26685537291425,-1.43567105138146));
#418=CARTESIAN_POINT('',(-2.54831500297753,-4.17589690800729,-1.68200981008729));
#419=CARTESIAN_POINT('',(-2.46702497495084,-4.12657040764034,-1.79895178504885));
#420=CARTESIAN_POINT('',(-2.27621742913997,-4.01518689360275,-2.03669083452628));
#421=CARTESIAN_POINT('',(-2.16426874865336,-3.95235046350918,-2.15517053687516));
#422=CARTESIAN_POINT('',(-1.92324507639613,-3.82568072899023,-2.37276837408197));
#423=CARTESIAN_POINT('',(-1.79415533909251,-3.76184660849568,-2.47186965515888));
#424=CARTESIAN_POINT('',(-1.52700320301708,-3.6422101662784,-2.64476720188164));
#425=CARTESIAN_POINT('',(-1.38971103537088,-3.58616592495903,-2.71958017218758));
#426=CARTESIAN_POINT('',(-1.10202420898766,-3.48481309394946,-2.84829695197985));
#427=CARTESIAN_POINT('',(-0.951651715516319,-3.43948680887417,-2.90223532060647));
#428=CARTESIAN_POINT('',(-0.668272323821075,-3.37324804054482,-2.97881254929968));
#429=CARTESIAN_POINT('',(-0.537042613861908,-3.34940288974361,-3.00534763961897));
#430=CARTESIAN_POINT('',(-0.337187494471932,-3.32517436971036,-3.03205239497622));
#431=CARTESIAN_POINT('',(-0.270072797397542,-3.3190214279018,-3.03877098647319));
#432=CARTESIAN_POINT('',(-0.135306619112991,-3.31078493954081,-3.04774423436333));
#433=CARTESIAN_POINT('',(-0.0676553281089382,-3.30870001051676,-3.05000040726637));
#434=CARTESIAN_POINT('',(0.,-3.30870065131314,-3.05));
#435=B_SPLINE_CURVE_WITH_KNOTS('',3,(#343,#344,#345,#346,#347,#348,#349,#350,#351,#352,#353,
#354,#355,#356,#357,#358,#359,#360,#361,#362,#363,#364,#365,#366,#367,#368,#369,#370,#371,#372,
#373,#374,#375,#376,#377,#378,#379,#380,#381,#382,#383,#384,#385,#386,#387,#388,#389,#390,#391,
#392,#393,#394,#395,#396,#397,#398,#399,#400,#401,#402,#403,#404,#405,#406,#407,#408,#409,#410,
#411,#412,#413,#414,#415,#416,#417,#418,#419,#420,#421,#422,#423,#424,#425,#426,#427,#428,#429,
#430,#431,#432,#433,#434),.UNSPECIFIED.,.T.,.F.,(4,2,2,2,2,2,2,2,2,2,2,2,2,2,2,2,2,2,2,2,2,2,2,
2,2,2,2,2,2,2,2,2,2,2,2,2,2,2,2,2,2,2,2,2,2,4),(0.,0.222074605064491,0.444173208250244,
0.888639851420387,1.32867397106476,1.76878136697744,2.28012572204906,2.79204704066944,
3.3816546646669,3.67634407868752,3.97091568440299,4.40924515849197,4.84723863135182,
5.28596638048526,5.72482295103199,6.1557338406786,6.58672656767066,7.06630172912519,
7.54643585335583,8.10749203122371,8.66823277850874,9.09600687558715,9.52299588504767,
9.95344853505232,10.3839130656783,10.7663784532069,11.1491951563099,11.7047959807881,
12.2614304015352,12.8257196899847,13.3891078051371,13.8528597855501,14.3163138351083,
14.7819661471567,15.247525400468,15.6758920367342,16.104326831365,16.5548361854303,
17.0055878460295,17.527655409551,18.0501750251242,18.5465955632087,19.0421906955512,
19.4481632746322,19.6511174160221,19.8540025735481),.UNSPECIFIED.);
#436=CARTESIAN_POINT('',(0.,-3.30870065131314,-3.05));
#437=VERTEX_POINT('',#436);
#438=EDGE_CURVE('E237',#437,#437,#435,.T.);
#439=ORIENTED_EDGE('',*,*,#438,.T.);
#440=EDGE_LOOP('',(#439));
#441=FACE_BOUND('',#440,.T.);
#442=ADVANCED_FACE('F159',(#342,#441),#245,.T.);
#443=CARTESIAN_POINT('',(0.,-18.,0.));
#444=DIRECTION('',(0.,-1.,0.));
#445=DIRECTION('',(0.,0.,-1.));
#446=AXIS2_PLACEMENT_3D('',#443,#444,#445);
#447=CYLINDRICAL_SURFACE('',#446,8.75);
#448=CARTESIAN_POINT('',(0.,-18.,0.));
#449=DIRECTION('',(0.,-1.,0.));
#450=DIRECTION('',(0.,0.,-1.));
#451=AXIS2_PLACEMENT_3D('',#448,#449,#450);
#452=CIRCLE('',#451,8.75);
#453=CARTESIAN_POINT('',(0.,-18.,-8.75));
#454=VERTEX_POINT('',#453);
#455=EDGE_CURVE('E281',#454,#454,#452,.T.);
#456=ORIENTED_EDGE('',*,*,#455,.F.);
#457=EDGE_LOOP('',(#456));
#458=FACE_BOUND('',#457,.T.);
#459=DIRECTION('',(0.,-1.,0.));
#460=VECTOR('',#459,1.);
#461=CARTESIAN_POINT('',(3.9,-18.,7.83278366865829));
#462=LINE('',#461,#460);
#463=CARTESIAN_POINT('',(3.9,-8.,7.83278366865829));
#464=VERTEX_POINT('',#463);
#465=CARTESIAN_POINT('',(3.9,-8.05467298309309,7.83278366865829));
#466=VERTEX_POINT('',#465);
#467=EDGE_CURVE('E278',#464,#466,#462,.T.);
#468=ORIENTED_EDGE('',*,*,#467,.F.);
#469=CARTESIAN_POINT('',(0.,-8.,0.));
#470=DIRECTION('',(0.,-1.,0.));
#471=DIRECTION('',(0.,0.,-1.));
#472=AXIS2_PLACEMENT_3D('',#469,#470,#471);
#473=CIRCLE('',#472,8.75);
#474=CARTESIAN_POINT('',(-3.9,-8.,7.83278366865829));
#475=VERTEX_POINT('',#474);
#476=EDGE_CURVE('E284',#464,#475,#473,.T.);
#477=ORIENTED_EDGE('',*,*,#476,.T.);
#478=DIRECTION('',(0.,-1.,0.));
#479=VECTOR('',#478,1.);
#480=CARTESIAN_POINT('',(-3.9,-18.,7.83278366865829));
#481=LINE('',#480,#479);
#482=CARTESIAN_POINT('',(-3.9,-8.05467298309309,7.83278366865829));
#483=VERTEX_POINT('',#482);
#484=EDGE_CURVE('E268',#483,#475,#481,.F.);
#485=ORIENTED_EDGE('',*,*,#484,.F.);
#486=CARTESIAN_POINT('',(-3.9,-8.05467298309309,-7.83278366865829));
#487=CARTESIAN_POINT('',(-4.12452384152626,-8.09737217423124,-7.721006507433));
#488=CARTESIAN_POINT('',(-4.34380093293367,-8.1426514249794,-7.5997666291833));
#489=CARTESIAN_POINT('',(-4.77055982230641,-8.23689755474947,-7.33939091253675));
#490=CARTESIAN_POINT('',(-4.97804428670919,-8.28586359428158,-7.20025914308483));
#491=CARTESIAN_POINT('',(-5.38011565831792,-8.38605555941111,-6.90500663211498));
#492=CARTESIAN_POINT('',(-5.57469632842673,-8.43728255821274,-6.74887776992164));
#493=CARTESIAN_POINT('',(-5.94972754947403,-8.54050248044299,-6.42069527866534));
#494=CARTESIAN_POINT('',(-6.13017736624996,-8.59249544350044,-6.24864082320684));
#495=CARTESIAN_POINT('',(-6.4758207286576,-8.69578877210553,-5.88967916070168));
#496=CARTESIAN_POINT('',(-6.64101593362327,-8.74708921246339,-5.7027735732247));
#497=CARTESIAN_POINT('',(-6.95509462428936,-8.8475918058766,-5.31520163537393));
#498=CARTESIAN_POINT('',(-7.10397859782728,-8.89679402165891,-5.11453569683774));
#499=CARTESIAN_POINT('',(-7.3843624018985,-8.99174565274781,-4.70065534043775));
#500=CARTESIAN_POINT('',(-7.51586399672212,-9.03749541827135,-4.4874421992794));
#501=CARTESIAN_POINT('',(-7.76039107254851,-9.12425375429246,-4.04988941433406));
#502=CARTESIAN_POINT('',(-7.87342610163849,-9.16526477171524,-3.82555559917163));
#503=CARTESIAN_POINT('',(-8.07907473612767,-9.24103260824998,-3.36942343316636));
#504=CARTESIAN_POINT('',(-8.17187940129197,-9.2758473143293,-3.13772094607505));
#505=CARTESIAN_POINT('',(-8.33757753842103,-9.33872146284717,-2.66640099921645));
#506=CARTESIAN_POINT('',(-8.41047104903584,-9.36678091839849,-2.42678355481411));
#507=CARTESIAN_POINT('',(-8.5355569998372,-9.41531310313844,-1.94152657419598));
#508=CARTESIAN_POINT('',(-8.58775595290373,-9.43578821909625,-1.69588895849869));
#509=CARTESIAN_POINT('',(-8.67089101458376,-9.46854701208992,-1.2005061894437));
#510=CARTESIAN_POINT('',(-8.70182846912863,-9.48083120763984,-0.950761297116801));
#511=CARTESIAN_POINT('',(-8.7407495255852,-9.49630702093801,-0.4658358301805));
#512=CARTESIAN_POINT('',(-8.750113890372,-9.50004546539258,-0.2307824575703));
#513=CARTESIAN_POINT('',(-8.7498840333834,-9.49995370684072,0.239307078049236));
#514=CARTESIAN_POINT('',(-8.7402907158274,-9.49612386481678,0.474343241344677));
#515=CARTESIAN_POINT('',(-8.70225130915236,-9.48100009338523,0.942599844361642));
#516=CARTESIAN_POINT('',(-8.67380828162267,-9.46970737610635,1.17582057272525));
#517=CARTESIAN_POINT('',(-8.59836743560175,-9.43996057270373,1.63877460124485));
#518=CARTESIAN_POINT('',(-8.55136958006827,-9.42150647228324,1.86850789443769));
#519=CARTESIAN_POINT('',(-8.44061471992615,-9.37843869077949,2.31748063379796));
#520=CARTESIAN_POINT('',(-8.37728079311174,-9.35398116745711,2.53683975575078));
#521=CARTESIAN_POINT('',(-8.23390957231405,-9.29929221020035,2.96937079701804));
#522=CARTESIAN_POINT('',(-8.153866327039,-9.26905871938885,3.18254048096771));
#523=CARTESIAN_POINT('',(-7.9777519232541,-9.20354769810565,3.60132955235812));
#524=CARTESIAN_POINT('',(-7.88168151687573,-9.16827040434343,3.80694929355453));
#525=CARTESIAN_POINT('',(-7.67419463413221,-9.09348021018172,4.2095784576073));
#526=CARTESIAN_POINT('',(-7.56277248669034,-9.05396574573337,4.40658466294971));
#527=CARTESIAN_POINT('',(-7.31951823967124,-8.96958509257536,4.80034457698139));
#528=CARTESIAN_POINT('',(-7.18695156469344,-8.92455123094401,4.99660873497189));
#529=CARTESIAN_POINT('',(-6.90662819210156,-8.83192026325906,5.37744590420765));
#530=CARTESIAN_POINT('',(-6.75886512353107,-8.78432208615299,5.5620139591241));
#531=CARTESIAN_POINT('',(-6.4491916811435,-8.68777999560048,5.91828375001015));
#532=CARTESIAN_POINT('',(-6.28729068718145,-8.63883698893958,6.08999387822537));
#533=CARTESIAN_POINT('',(-5.95018583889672,-8.54078643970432,6.4197690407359));
#534=CARTESIAN_POINT('',(-5.77497970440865,-8.4916788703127,6.5778317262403));
#535=CARTESIAN_POINT('',(-5.33439681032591,-8.37371263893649,6.94407214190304));
#536=CARTESIAN_POINT('',(-5.06252636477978,-8.30539786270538,7.14473831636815));
#537=CARTESIAN_POINT('',(-4.63830883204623,-8.20738306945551,7.42139553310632));
#538=CARTESIAN_POINT('',(-4.49422811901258,-8.17546615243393,7.50952743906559));
#539=CARTESIAN_POINT('',(-4.20090392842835,-8.11353556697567,7.67746300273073));
#540=CARTESIAN_POINT('',(-4.05166060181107,-8.08352184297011,7.7572669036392));
#541=CARTESIAN_POINT('',(-3.9,-8.0546729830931,7.83278366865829));
#542=B_SPLINE_CURVE_WITH_KNOTS('',3,(#486,#487,#488,#489,#490,#491,#492,#493,#494,#495,#496,
#497,#498,#499,#500,#501,#502,#503,#504,#505,#506,#507,#508,#509,#510,#511,#512,#513,#514,#515,
#516,#517,#518,#519,#520,#521,#522,#523,#524,#525,#526,#527,#528,#529,#530,#531,#532,#533,#534,
#535,#536,#537,#538,#539,#540,#541),.UNSPECIFIED.,.F.,.F.,(4,2,2,2,2,2,2,2,2,2,2,2,2,2,2,2,2,2,
2,2,2,2,2,2,2,2,2,4),(0.,0.762954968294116,1.5257367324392,2.28888454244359,3.0520719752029,
3.81517629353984,4.57825778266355,5.34126176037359,6.10386997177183,6.85892977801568,
7.61398811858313,8.36880864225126,9.1235813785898,9.82851622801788,10.5334174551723,
11.2382042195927,11.9429923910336,12.6310960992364,13.3194453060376,14.0077622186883,
14.6963340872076,15.4187923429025,16.14155472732,16.8638411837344,17.5862517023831,
18.6179068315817,19.1333253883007,19.6487288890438),.UNSPECIFIED.);
#543=CARTESIAN_POINT('',(-3.9,-8.05467298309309,-7.83278366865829));
#544=VERTEX_POINT('',#543);
#545=EDGE_CURVE('E123',#544,#483,#542,.T.);
#546=ORIENTED_EDGE('',*,*,#545,.F.);
#547=DIRECTION('',(0.,-1.,0.));
#548=VECTOR('',#547,1.);
#549=CARTESIAN_POINT('',(-3.9,-18.,-7.83278366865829));
#550=LINE('',#549,#548);
#551=CARTESIAN_POINT('',(-3.9,-8.,-7.83278366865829));
#552=VERTEX_POINT('',#551);
#553=EDGE_CURVE('E270',#552,#544,#550,.T.);
#554=ORIENTED_EDGE('',*,*,#553,.F.);
#555=CARTESIAN_POINT('',(3.9,-8.,-7.83278366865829));
#556=VERTEX_POINT('',#555);
#557=EDGE_CURVE('E285',#552,#556,#473,.T.);
#558=ORIENTED_EDGE('',*,*,#557,.T.);
#559=DIRECTION('',(0.,-1.,0.));
#560=VECTOR('',#559,1.);
#561=CARTESIAN_POINT('',(3.9,-18.,-7.83278366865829));
#562=LINE('',#561,#560);
#563=CARTESIAN_POINT('',(3.9,-8.05467298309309,-7.83278366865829));
#564=VERTEX_POINT('',#563);
#565=EDGE_CURVE('E276',#564,#556,#562,.F.);
#566=ORIENTED_EDGE('',*,*,#565,.F.);
#567=CARTESIAN_POINT('',(3.9,-8.05467298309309,7.83278366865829));
#568=CARTESIAN_POINT('',(4.12452384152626,-8.09737217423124,7.721006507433));
#569=CARTESIAN_POINT('',(4.34380093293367,-8.1426514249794,7.5997666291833));
#570=CARTESIAN_POINT('',(4.77055982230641,-8.23689755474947,7.33939091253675));
#571=CARTESIAN_POINT('',(4.97804428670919,-8.28586359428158,7.20025914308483));
#572=CARTESIAN_POINT('',(5.38011565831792,-8.38605555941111,6.90500663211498));
#573=CARTESIAN_POINT('',(5.57469632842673,-8.43728255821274,6.74887776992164));
#574=CARTESIAN_POINT('',(5.94972754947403,-8.54050248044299,6.42069527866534));
#575=CARTESIAN_POINT('',(6.13017736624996,-8.59249544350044,6.24864082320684));
#576=CARTESIAN_POINT('',(6.4758207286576,-8.69578877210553,5.88967916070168));
#577=CARTESIAN_POINT('',(6.64101593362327,-8.74708921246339,5.7027735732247));
#578=CARTESIAN_POINT('',(6.95509462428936,-8.8475918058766,5.31520163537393));
#579=CARTESIAN_POINT('',(7.10397859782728,-8.89679402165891,5.11453569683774));
#580=CARTESIAN_POINT('',(7.3843624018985,-8.99174565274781,4.70065534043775));
#581=CARTESIAN_POINT('',(7.51586399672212,-9.03749541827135,4.4874421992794));
#582=CARTESIAN_POINT('',(7.76039107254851,-9.12425375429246,4.04988941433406));
#583=CARTESIAN_POINT('',(7.87342610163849,-9.16526477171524,3.82555559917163));
#584=CARTESIAN_POINT('',(8.07907473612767,-9.24103260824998,3.36942343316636));
#585=CARTESIAN_POINT('',(8.17187940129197,-9.2758473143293,3.13772094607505));
#586=CARTESIAN_POINT('',(8.33757753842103,-9.33872146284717,2.66640099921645));
#587=CARTESIAN_POINT('',(8.41047104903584,-9.36678091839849,2.42678355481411));
#588=CARTESIAN_POINT('',(8.5355569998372,-9.41531310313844,1.94152657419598));
#589=CARTESIAN_POINT('',(8.58775595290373,-9.43578821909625,1.69588895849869));
#590=CARTESIAN_POINT('',(8.67089101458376,-9.46854701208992,1.2005061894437));
#591=CARTESIAN_POINT('',(8.70182846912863,-9.48083120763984,0.950761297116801));
#592=CARTESIAN_POINT('',(8.7407495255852,-9.49630702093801,0.4658358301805));
#593=CARTESIAN_POINT('',(8.750113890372,-9.50004546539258,0.2307824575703));
#594=CARTESIAN_POINT('',(8.7498840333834,-9.49995370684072,-0.239307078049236));
#595=CARTESIAN_POINT('',(8.7402907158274,-9.49612386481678,-0.474343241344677));
#596=CARTESIAN_POINT('',(8.70225130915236,-9.48100009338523,-0.942599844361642));
#597=CARTESIAN_POINT('',(8.67380828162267,-9.46970737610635,-1.17582057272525));
#598=CARTESIAN_POINT('',(8.59836743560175,-9.43996057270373,-1.63877460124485));
#599=CARTESIAN_POINT('',(8.55136958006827,-9.42150647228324,-1.86850789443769));
#600=CARTESIAN_POINT('',(8.44061471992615,-9.37843869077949,-2.31748063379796));
#601=CARTESIAN_POINT('',(8.37728079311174,-9.35398116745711,-2.53683975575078));
#602=CARTESIAN_POINT('',(8.23390957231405,-9.29929221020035,-2.96937079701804));
#603=CARTESIAN_POINT('',(8.153866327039,-9.26905871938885,-3.18254048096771));
#604=CARTESIAN_POINT('',(7.9777519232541,-9.20354769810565,-3.60132955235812));
#605=CARTESIAN_POINT('',(7.88168151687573,-9.16827040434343,-3.80694929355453));
#606=CARTESIAN_POINT('',(7.67419463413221,-9.09348021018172,-4.2095784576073));
#607=CARTESIAN_POINT('',(7.56277248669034,-9.05396574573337,-4.40658466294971));
#608=CARTESIAN_POINT('',(7.31951823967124,-8.96958509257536,-4.80034457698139));
#609=CARTESIAN_POINT('',(7.18695156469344,-8.92455123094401,-4.99660873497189));
#610=CARTESIAN_POINT('',(6.90662819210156,-8.83192026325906,-5.37744590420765));
#611=CARTESIAN_POINT('',(6.75886512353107,-8.78432208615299,-5.5620139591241));
#612=CARTESIAN_POINT('',(6.4491916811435,-8.68777999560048,-5.91828375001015));
#613=CARTESIAN_POINT('',(6.28729068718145,-8.63883698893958,-6.08999387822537));
#614=CARTESIAN_POINT('',(5.95018583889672,-8.54078643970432,-6.4197690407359));
#615=CARTESIAN_POINT('',(5.77497970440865,-8.4916788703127,-6.5778317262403));
#616=CARTESIAN_POINT('',(5.33439681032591,-8.37371263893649,-6.94407214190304));
#617=CARTESIAN_POINT('',(5.06252636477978,-8.30539786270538,-7.14473831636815));
#618=CARTESIAN_POINT('',(4.63830883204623,-8.20738306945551,-7.42139553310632));
#619=CARTESIAN_POINT('',(4.49422811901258,-8.17546615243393,-7.50952743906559));
#620=CARTESIAN_POINT('',(4.20090392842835,-8.11353556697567,-7.67746300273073));
#621=CARTESIAN_POINT('',(4.05166060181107,-8.08352184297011,-7.7572669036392));
#622=CARTESIAN_POINT('',(3.9,-8.0546729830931,-7.83278366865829));
#623=B_SPLINE_CURVE_WITH_KNOTS('',3,(#567,#568,#569,#570,#571,#572,#573,#574,#575,#576,#577,
#578,#579,#580,#581,#582,#583,#584,#585,#586,#587,#588,#589,#590,#591,#592,#593,#594,#595,#596,
#597,#598,#599,#600,#601,#602,#603,#604,#605,#606,#607,#608,#609,#610,#611,#612,#613,#614,#615,
#616,#617,#618,#619,#620,#621,#622),.UNSPECIFIED.,.F.,.F.,(4,2,2,2,2,2,2,2,2,2,2,2,2,2,2,2,2,2,
2,2,2,2,2,2,2,2,2,4),(0.,0.762954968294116,1.5257367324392,2.28888454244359,3.0520719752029,
3.81517629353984,4.57825778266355,5.34126176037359,6.10386997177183,6.85892977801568,
7.61398811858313,8.36880864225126,9.1235813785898,9.82851622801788,10.5334174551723,
11.2382042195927,11.9429923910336,12.6310960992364,13.3194453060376,14.0077622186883,
14.6963340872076,15.4187923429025,16.14155472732,16.8638411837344,17.5862517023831,
18.6179068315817,19.1333253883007,19.6487288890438),.UNSPECIFIED.);
#624=EDGE_CURVE('E114',#466,#564,#623,.T.);
#625=ORIENTED_EDGE('',*,*,#624,.F.);
#626=EDGE_LOOP('',(#468,#477,#485,#546,#554,#558,#566,#625));
#627=FACE_BOUND('',#626,.T.);
#628=ADVANCED_FACE('F130',(#458,#627),#447,.T.);
#629=CARTESIAN_POINT('',(0.,-8.,-3.9));
#630=DIRECTION('',(0.,-1.,0.));
#631=DIRECTION('',(0.,0.,-1.));
#632=AXIS2_PLACEMENT_3D('',#629,#630,#631);
#633=PLANE('',#632);
#634=DIRECTION('',(0.,0.,1.));
#635=VECTOR('',#634,1.);
#636=CARTESIAN_POINT('',(3.9,-8.,-3.9));
#637=LINE('',#636,#635);
#638=CARTESIAN_POINT('',(3.9,-8.,0.));
#639=VERTEX_POINT('',#638);
#640=EDGE_CURVE('E273',#639,#464,#637,.T.);
#641=ORIENTED_EDGE('',*,*,#640,.F.);
#642=CARTESIAN_POINT('',(0.,-8.,0.));
#643=DIRECTION('',(0.,-1.,0.));
#644=DIRECTION('',(0.,0.,-1.));
#645=AXIS2_PLACEMENT_3D('',#642,#643,#644);
#646=CIRCLE('',#645,3.9);
#647=CARTESIAN_POINT('',(-3.9,-8.,0.));
#648=VERTEX_POINT('',#647);
#649=EDGE_CURVE('E288',#639,#648,#646,.T.);
#650=ORIENTED_EDGE('',*,*,#649,.T.);
#651=DIRECTION('',(0.,0.,-1.));
#652=VECTOR('',#651,1.);
#653=CARTESIAN_POINT('',(-3.9,-8.,-3.9));
#654=LINE('',#653,#652);
#655=EDGE_CURVE('E267',#475,#648,#654,.T.);
#656=ORIENTED_EDGE('',*,*,#655,.F.);
#657=ORIENTED_EDGE('',*,*,#476,.F.);
#658=EDGE_LOOP('',(#641,#650,#656,#657));
#659=FACE_BOUND('',#658,.T.);
#660=ADVANCED_FACE('F318',(#659),#633,.F.);
#661=EDGE_CURVE('E264',#648,#552,#654,.T.);
#662=ORIENTED_EDGE('',*,*,#661,.F.);
#663=EDGE_CURVE('E35',#648,#639,#646,.T.);
#664=ORIENTED_EDGE('',*,*,#663,.T.);
#665=EDGE_CURVE('E275',#556,#639,#637,.T.);
#666=ORIENTED_EDGE('',*,*,#665,.F.);
#667=ORIENTED_EDGE('',*,*,#557,.F.);
#668=EDGE_LOOP('',(#662,#664,#666,#667));
#669=FACE_BOUND('',#668,.T.);
#670=ADVANCED_FACE('F322',(#669),#633,.F.);
#671=CARTESIAN_POINT('',(-3.9,7.,0.));
#672=DIRECTION('',(-1.,0.,0.));
#673=DIRECTION('',(0.,0.,1.));
#674=AXIS2_PLACEMENT_3D('',#671,#672,#673);
#675=PLANE('',#674);
#676=CARTESIAN_POINT('',(-3.9,0.,0.));
#677=DIRECTION('',(-1.,0.,0.));
#678=DIRECTION('',(0.,0.,1.));
#679=AXIS2_PLACEMENT_3D('',#676,#677,#678);
#680=CIRCLE('',#679,4.5);
#681=CARTESIAN_POINT('',(-3.9,0.,4.5));
#682=VERTEX_POINT('',#681);
#683=EDGE_CURVE('E505',#682,#682,#680,.F.);
#684=ORIENTED_EDGE('',*,*,#683,.T.);
#685=EDGE_LOOP('',(#684));
#686=FACE_BOUND('',#685,.T.);
#687=ORIENTED_EDGE('',*,*,#138,.F.);
#688=EDGE_LOOP('',(#687));
#689=FACE_BOUND('',#688,.T.);
#690=ADVANCED_FACE('F16',(#686,#689),#675,.T.);
#691=CARTESIAN_POINT('',(3.9,4.5,0.));
#692=DIRECTION('',(1.,0.,0.));
#693=DIRECTION('',(0.,0.,-1.));
#694=AXIS2_PLACEMENT_3D('',#691,#692,#693);
#695=PLANE('',#694);
#696=ORIENTED_EDGE('',*,*,#147,.T.);
#697=EDGE_LOOP('',(#696));
#698=FACE_BOUND('',#697,.T.);
#699=CARTESIAN_POINT('',(3.9,0.,0.));
#700=DIRECTION('',(1.,0.,0.));
#701=DIRECTION('',(0.,0.,-1.));
#702=AXIS2_PLACEMENT_3D('',#699,#700,#701);
#703=CIRCLE('',#702,4.5);
#704=CARTESIAN_POINT('',(3.9,0.,-4.5));
#705=VERTEX_POINT('',#704);
#706=EDGE_CURVE('E295',#705,#705,#703,.T.);
#707=ORIENTED_EDGE('',*,*,#706,.F.);
#708=EDGE_LOOP('',(#707));
#709=FACE_BOUND('',#708,.T.);
#710=ADVANCED_FACE('F145',(#698,#709),#695,.T.);
#711=CARTESIAN_POINT('',(0.,-18.,-8.75));
#712=DIRECTION('',(0.,1.,0.));
#713=DIRECTION('',(0.,0.,1.));
#714=AXIS2_PLACEMENT_3D('',#711,#712,#713);
#715=PLANE('',#714);
#716=CARTESIAN_POINT('',(0.,-18.,0.));
#717=DIRECTION('',(0.,-1.,0.));
#718=DIRECTION('',(0.,0.,-1.));
#719=AXIS2_PLACEMENT_3D('',#716,#717,#718);
#720=CIRCLE('',#719,3.05);
#721=CARTESIAN_POINT('',(0.,-18.,-3.05));
#722=VERTEX_POINT('',#721);
#723=EDGE_CURVE('E506',#722,#722,#720,.T.);
#724=ORIENTED_EDGE('',*,*,#723,.F.);
#725=EDGE_LOOP('',(#724));
#726=FACE_BOUND('',#725,.T.);
#727=ORIENTED_EDGE('',*,*,#455,.T.);
#728=EDGE_LOOP('',(#727));
#729=FACE_BOUND('',#728,.T.);
#730=ADVANCED_FACE('F142',(#726,#729),#715,.F.);
#731=CARTESIAN_POINT('',(0.,-18.,0.));
#732=DIRECTION('',(0.,-1.,0.));
#733=DIRECTION('',(0.,0.,-1.));
#734=AXIS2_PLACEMENT_3D('',#731,#732,#733);
#735=CYLINDRICAL_SURFACE('',#734,3.9);
#736=ORIENTED_EDGE('',*,*,#663,.F.);
#737=ORIENTED_EDGE('',*,*,#649,.F.);
#738=EDGE_LOOP('',(#736,#737));
#739=FACE_BOUND('',#738,.T.);
#740=ORIENTED_EDGE('',*,*,#131,.F.);
#741=ORIENTED_EDGE('',*,*,#140,.F.);
#742=EDGE_LOOP('',(#740,#741));
#743=FACE_BOUND('',#742,.T.);
#744=ADVANCED_FACE('F144',(#739,#743),#735,.T.);
#745=CARTESIAN_POINT('',(-3.9,9.4470989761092,0.));
#746=DIRECTION('',(-1.,0.,0.));
#747=DIRECTION('',(0.,0.,1.));
#748=AXIS2_PLACEMENT_3D('',#745,#746,#747);
#749=PLANE('',#748);
#750=ORIENTED_EDGE('',*,*,#553,.T.);
#751=CARTESIAN_POINT('',(-3.9,12.4470989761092,0.));
#752=DIRECTION('',(-1.,0.,0.));
#753=DIRECTION('',(0.,0.,1.));
#754=AXIS2_PLACEMENT_3D('',#751,#752,#753);
#755=CIRCLE('',#754,21.9470989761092);
#756=EDGE_CURVE('E239',#544,#483,#755,.T.);
#757=ORIENTED_EDGE('',*,*,#756,.T.);
#758=ORIENTED_EDGE('',*,*,#484,.T.);
#759=ORIENTED_EDGE('',*,*,#655,.T.);
#760=ORIENTED_EDGE('',*,*,#661,.T.);
#761=EDGE_LOOP('',(#750,#757,#758,#759,#760));
#762=FACE_BOUND('',#761,.T.);
#763=ADVANCED_FACE('F152',(#762),#749,.T.);
#764=CARTESIAN_POINT('',(-17.5,12.4470989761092,0.));
#765=DIRECTION('',(-1.,0.,0.));
#766=DIRECTION('',(0.,0.,1.));
#767=AXIS2_PLACEMENT_3D('',#764,#765,#766);
#768=CYLINDRICAL_SURFACE('',#767,21.9470989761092);
#769=ORIENTED_EDGE('',*,*,#756,.F.);
#770=ORIENTED_EDGE('',*,*,#545,.T.);
#771=EDGE_LOOP('',(#769,#770));
#772=FACE_BOUND('',#771,.T.);
#773=ADVANCED_FACE('F139',(#772),#768,.F.);
#774=CARTESIAN_POINT('',(-17.5,12.4470989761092,0.));
#775=DIRECTION('',(-1.,0.,0.));
#776=DIRECTION('',(0.,0.,1.));
#777=AXIS2_PLACEMENT_3D('',#774,#775,#776);
#778=CYLINDRICAL_SURFACE('',#777,21.9470989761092);
#779=CARTESIAN_POINT('',(3.9,12.4470989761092,0.));
#780=DIRECTION('',(-1.,0.,0.));
#781=DIRECTION('',(0.,0.,1.));
#782=AXIS2_PLACEMENT_3D('',#779,#780,#781);
#783=CIRCLE('',#782,21.9470989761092);
#784=EDGE_CURVE('E261',#564,#466,#783,.T.);
#785=ORIENTED_EDGE('',*,*,#784,.T.);
#786=ORIENTED_EDGE('',*,*,#624,.T.);
#787=EDGE_LOOP('',(#785,#786));
#788=FACE_BOUND('',#787,.T.);
#789=ADVANCED_FACE('F134',(#788),#778,.F.);
#790=CARTESIAN_POINT('',(3.9,-9.5,0.));
#791=DIRECTION('',(1.,0.,0.));
#792=DIRECTION('',(0.,0.,-1.));
#793=AXIS2_PLACEMENT_3D('',#790,#791,#792);
#794=PLANE('',#793);
#795=ORIENTED_EDGE('',*,*,#467,.T.);
#796=ORIENTED_EDGE('',*,*,#784,.F.);
#797=ORIENTED_EDGE('',*,*,#565,.T.);
#798=ORIENTED_EDGE('',*,*,#665,.T.);
#799=ORIENTED_EDGE('',*,*,#640,.T.);
#800=EDGE_LOOP('',(#795,#796,#797,#798,#799));
#801=FACE_BOUND('',#800,.T.);
#802=ADVANCED_FACE('F138',(#801),#794,.T.);
#803=CARTESIAN_POINT('',(0.,-18.,0.));
#804=DIRECTION('',(0.,-1.,0.));
#805=DIRECTION('',(0.,0.,-1.));
#806=AXIS2_PLACEMENT_3D('',#803,#804,#805);
#807=CYLINDRICAL_SURFACE('',#806,3.05);
#808=ORIENTED_EDGE('',*,*,#723,.T.);
#809=EDGE_LOOP('',(#808));
#810=FACE_BOUND('',#809,.T.);
#811=ORIENTED_EDGE('',*,*,#438,.F.);
#812=EDGE_LOOP('',(#811));
#813=FACE_BOUND('',#812,.T.);
#814=ADVANCED_FACE('F203',(#810,#813),#807,.F.);
#815=CARTESIAN_POINT('',(9.,0.,0.));
#816=DIRECTION('',(1.,0.,0.));
#817=DIRECTION('',(0.,0.,-1.));
#818=AXIS2_PLACEMENT_3D('',#815,#816,#817);
#819=PLANE('',#818);
#820=CARTESIAN_POINT('',(9.,0.,0.));
#821=DIRECTION('',(1.,0.,0.));
#822=DIRECTION('',(0.,0.,-1.));
#823=AXIS2_PLACEMENT_3D('',#820,#821,#822);
#824=CIRCLE('',#823,4.5);
#825=CARTESIAN_POINT('',(9.,0.,-4.5));
#826=VERTEX_POINT('',#825);
#827=EDGE_CURVE('E191',#826,#826,#824,.T.);
#828=ORIENTED_EDGE('',*,*,#827,.T.);
#829=EDGE_LOOP('',(#828));
#830=FACE_BOUND('',#829,.T.);
#831=ADVANCED_FACE('F200',(#830),#819,.T.);
#832=ORIENTED_EDGE('',*,*,#706,.T.);
#833=EDGE_LOOP('',(#832));
#834=FACE_BOUND('',#833,.T.);
#835=ORIENTED_EDGE('',*,*,#827,.F.);
#836=EDGE_LOOP('',(#835));
#837=FACE_BOUND('',#836,.T.);
#838=ADVANCED_FACE('F168',(#834,#837),#245,.T.);
#839=ORIENTED_EDGE('',*,*,#683,.F.);
#840=EDGE_LOOP('',(#839));
#841=FACE_BOUND('',#840,.T.);
#842=CARTESIAN_POINT('',(-9.,0.,0.));
#843=DIRECTION('',(1.,0.,0.));
#844=DIRECTION('',(0.,0.,-1.));
#845=AXIS2_PLACEMENT_3D('',#842,#843,#844);
#846=CIRCLE('',#845,4.5);
#847=CARTESIAN_POINT('',(-9.,0.,-4.5));
#848=VERTEX_POINT('',#847);
#849=EDGE_CURVE('E188',#848,#848,#846,.T.);
#850=ORIENTED_EDGE('',*,*,#849,.T.);
#851=EDGE_LOOP('',(#850));
#852=FACE_BOUND('',#851,.T.);
#853=ADVANCED_FACE('F206',(#841,#852),#245,.T.);
#854=CARTESIAN_POINT('',(-9.,0.,0.));
#855=DIRECTION('',(1.,0.,0.));
#856=DIRECTION('',(0.,0.,-1.));
#857=AXIS2_PLACEMENT_3D('',#854,#855,#856);
#858=PLANE('',#857);
#859=ORIENTED_EDGE('',*,*,#849,.F.);
#860=EDGE_LOOP('',(#859));
#861=FACE_BOUND('',#860,.T.);
#862=ADVANCED_FACE('F197',(#861),#858,.F.);
#863=CARTESIAN_POINT('',(0.,-5.,0.));
#864=DIRECTION('',(0.,-1.,0.));
#865=DIRECTION('',(0.,0.,-1.));
#866=AXIS2_PLACEMENT_3D('',#863,#864,#865);
#867=CYLINDRICAL_SURFACE('',#866,2.5);
#868=CARTESIAN_POINT('',(1.4142135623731,4.,2.06155281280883));
#869=CARTESIAN_POINT('',(1.30921473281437,3.96283440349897,2.1336339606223));
#870=CARTESIAN_POINT('',(1.19805601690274,3.92718409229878,2.19802650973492));
#871=CARTESIAN_POINT('',(0.964865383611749,3.86243911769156,2.30994101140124));
#872=CARTESIAN_POINT('',(0.842766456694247,3.83338934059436,2.35734864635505));
#873=CARTESIAN_POINT('',(0.589954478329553,3.78584220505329,2.432986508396));
#874=CARTESIAN_POINT('',(0.459201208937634,3.76739862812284,2.46111913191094));
#875=CARTESIAN_POINT('',(0.194154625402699,3.74438364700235,2.49600974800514));
#876=CARTESIAN_POINT('',(0.059878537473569,3.73975415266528,2.50285725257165));
#877=CARTESIAN_POINT('',(-0.194311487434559,3.74475696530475,2.49535244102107));
#878=CARTESIAN_POINT('',(-0.314321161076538,3.75301182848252,2.48304800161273));
#879=CARTESIAN_POINT('',(-0.550520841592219,3.78011178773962,2.44158888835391));
#880=CARTESIAN_POINT('',(-0.666696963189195,3.79899168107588,2.41237883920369));
#881=CARTESIAN_POINT('',(-0.893689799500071,3.84527438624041,2.33790497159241));
#882=CARTESIAN_POINT('',(-1.00441211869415,3.8727896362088,2.29242818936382));
#883=CARTESIAN_POINT('',(-1.21650308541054,3.93313533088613,2.18725214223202));
#884=CARTESIAN_POINT('',(-1.31792246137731,3.96593388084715,2.12763726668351));
#885=CARTESIAN_POINT('',(-1.4142135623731,4.,2.06155281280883));
#886=B_SPLINE_CURVE_WITH_KNOTS('',3,(#868,#869,#870,#871,#872,#873,#874,#875,#876,#877,#878,
#879,#880,#881,#882,#883,#884,#885),.UNSPECIFIED.,.F.,.F.,(4,2,2,2,2,2,2,2,4),(0.,
0.398082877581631,0.798796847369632,1.20152522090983,1.60255766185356,1.96356027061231,
2.32575211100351,2.69287059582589,3.0578506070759),.UNSPECIFIED.);
#887=CARTESIAN_POINT('',(1.4142135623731,4.,2.06155281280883));
#888=VERTEX_POINT('',#887);
#889=CARTESIAN_POINT('',(-1.4142135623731,4.,2.06155281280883));
#890=VERTEX_POINT('',#889);
#891=EDGE_CURVE('E98',#888,#890,#886,.T.);
#892=ORIENTED_EDGE('',*,*,#891,.F.);
#893=CARTESIAN_POINT('',(0.,4.,0.));
#894=DIRECTION('',(0.,-1.,0.));
#895=DIRECTION('',(0.,0.,-1.));
#896=AXIS2_PLACEMENT_3D('',#893,#894,#895);
#897=CIRCLE('',#896,2.5);
#898=EDGE_CURVE('E189',#888,#890,#897,.T.);
#899=ORIENTED_EDGE('',*,*,#898,.T.);
#900=EDGE_LOOP('',(#892,#899));
#901=FACE_BOUND('',#900,.T.);
#902=CARTESIAN_POINT('',(0.,4.,0.));
#903=DIRECTION('',(0.,-1.,0.));
#904=DIRECTION('',(0.,0.,-1.));
#905=AXIS2_PLACEMENT_3D('',#902,#903,#904);
#906=CIRCLE('',#905,2.5);
#907=CARTESIAN_POINT('',(1.41421356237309,4.,-2.06155281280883));
#908=VERTEX_POINT('',#907);
#909=CARTESIAN_POINT('',(-1.4142135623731,4.,-2.06155281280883));
#910=VERTEX_POINT('',#909);
#911=EDGE_CURVE('E9',#908,#910,#906,.F.);
#912=ORIENTED_EDGE('',*,*,#911,.F.);
#913=CARTESIAN_POINT('',(-1.41421356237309,4.,-2.06155281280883));
#914=CARTESIAN_POINT('',(-1.30921473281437,3.96283440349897,-2.1336339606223));
#915=CARTESIAN_POINT('',(-1.19805601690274,3.92718409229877,-2.19802650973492));
#916=CARTESIAN_POINT('',(-0.964865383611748,3.86243911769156,-2.30994101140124));
#917=CARTESIAN_POINT('',(-0.842766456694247,3.83338934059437,-2.35734864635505));
#918=CARTESIAN_POINT('',(-0.589954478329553,3.78584220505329,-2.432986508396));
#919=CARTESIAN_POINT('',(-0.459201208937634,3.76739862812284,-2.46111913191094));
#920=CARTESIAN_POINT('',(-0.1941546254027,3.74438364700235,-2.49600974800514));
#921=CARTESIAN_POINT('',(-0.0598785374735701,3.73975415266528,-2.50285725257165));
#922=CARTESIAN_POINT('',(0.194311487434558,3.74475696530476,-2.49535244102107));
#923=CARTESIAN_POINT('',(0.314321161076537,3.75301182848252,-2.48304800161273));
#924=CARTESIAN_POINT('',(0.550520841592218,3.78011178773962,-2.44158888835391));
#925=CARTESIAN_POINT('',(0.666696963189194,3.79899168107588,-2.41237883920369));
#926=CARTESIAN_POINT('',(0.89368979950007,3.84527438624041,-2.33790497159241));
#927=CARTESIAN_POINT('',(1.00441211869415,3.8727896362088,-2.29242818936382));
#928=CARTESIAN_POINT('',(1.21650308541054,3.93313533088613,-2.18725214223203));
#929=CARTESIAN_POINT('',(1.31792246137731,3.96593388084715,-2.12763726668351));
#930=CARTESIAN_POINT('',(1.41421356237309,4.,-2.06155281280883));
#931=B_SPLINE_CURVE_WITH_KNOTS('',3,(#913,#914,#915,#916,#917,#918,#919,#920,#921,#922,#923,
#924,#925,#926,#927,#928,#929,#930),.UNSPECIFIED.,.F.,.F.,(4,2,2,2,2,2,2,2,4),(0.,
0.39808287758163,0.798796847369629,1.20152522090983,1.60255766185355,1.9635602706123,
2.32575211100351,2.69287059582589,3.0578506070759),.UNSPECIFIED.);
#932=EDGE_CURVE('E92',#910,#908,#931,.T.);
#933=ORIENTED_EDGE('',*,*,#932,.F.);
#934=EDGE_LOOP('',(#912,#933));
#935=FACE_BOUND('',#934,.T.);
#936=ORIENTED_EDGE('',*,*,#236,.F.);
#937=EDGE_LOOP('',(#936));
#938=FACE_BOUND('',#937,.T.);
#939=ORIENTED_EDGE('',*,*,#339,.F.);
#940=EDGE_LOOP('',(#939));
#941=FACE_BOUND('',#940,.T.);
#942=ADVANCED_FACE('F93',(#901,#935,#938,#941),#867,.F.);
#943=DIRECTION('',(1.,0.,0.));
#944=VECTOR('',#943,1.);
#945=CARTESIAN_POINT('',(3.9,4.,2.06155281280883));
#946=LINE('',#945,#944);
#947=CARTESIAN_POINT('',(2.2477766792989,4.,2.06155281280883));
#948=VERTEX_POINT('',#947);
#949=EDGE_CURVE('E109',#948,#888,#946,.F.);
#950=ORIENTED_EDGE('',*,*,#949,.T.);
#951=ORIENTED_EDGE('',*,*,#891,.T.);
#952=CARTESIAN_POINT('',(-2.2477766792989,4.,2.06155281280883));
#953=VERTEX_POINT('',#952);
#954=EDGE_CURVE('E113',#890,#953,#946,.F.);
#955=ORIENTED_EDGE('',*,*,#954,.T.);
#956=CARTESIAN_POINT('',(-2.2477766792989,4.,2.06155281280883));
#957=CARTESIAN_POINT('',(-2.18870941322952,3.96682476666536,2.12593900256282));
#958=CARTESIAN_POINT('',(-2.12705096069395,3.93305483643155,2.18762834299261));
#959=CARTESIAN_POINT('',(-1.99874333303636,3.86516153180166,2.30545762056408));
#960=CARTESIAN_POINT('',(-1.93209122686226,3.83103796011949,2.36159425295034));
#961=CARTESIAN_POINT('',(-1.79343359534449,3.76300806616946,2.46856778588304));
#962=CARTESIAN_POINT('',(-1.72138506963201,3.72910650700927,2.51935210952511));
#963=CARTESIAN_POINT('',(-1.57269548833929,3.66284632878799,2.61475280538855));
#964=CARTESIAN_POINT('',(-1.4960558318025,3.63048724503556,2.65937104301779));
#965=CARTESIAN_POINT('',(-1.28908396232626,3.54899340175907,2.76797473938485));
#966=CARTESIAN_POINT('',(-1.15506092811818,3.50197453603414,2.82669658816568));
#967=CARTESIAN_POINT('',(-0.877003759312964,3.4204011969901,2.9248870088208));
#968=CARTESIAN_POINT('',(-0.733011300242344,3.385798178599,2.96443078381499));
#969=CARTESIAN_POINT('',(-0.460527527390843,3.33833884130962,3.01771031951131));
#970=CARTESIAN_POINT('',(-0.333088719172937,3.32294472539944,3.03449431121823));
#971=CARTESIAN_POINT('',(-0.0761818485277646,3.307100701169,3.05176049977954));
#972=CARTESIAN_POINT('',(0.0532853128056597,3.30664433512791,3.05224974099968));
#973=CARTESIAN_POINT('',(0.310178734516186,3.32073117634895,3.03691226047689));
#974=CARTESIAN_POINT('',(0.437607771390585,3.33525182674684,3.02111007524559));
#975=CARTESIAN_POINT('',(0.687505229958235,3.37711579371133,2.97423152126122));
#976=CARTESIAN_POINT('',(0.809966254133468,3.40447752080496,2.94313321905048));
#977=CARTESIAN_POINT('',(1.08867524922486,3.47979949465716,2.85402192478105));
#978=CARTESIAN_POINT('',(1.24208423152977,3.53160669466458,2.7904336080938));
#979=CARTESIAN_POINT('',(1.53407407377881,3.64453813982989,2.64122776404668));
#980=CARTESIAN_POINT('',(1.67263287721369,3.70567592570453,2.55557809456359));
#981=CARTESIAN_POINT('',(1.88374623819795,3.80670623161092,2.40083120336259));
#982=CARTESIAN_POINT('',(1.96129972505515,3.84579576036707,2.3379039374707));
#983=CARTESIAN_POINT('',(2.10958838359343,3.92351112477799,2.20498836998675));
#984=CARTESIAN_POINT('',(2.180354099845,3.96213827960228,2.13503491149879));
#985=CARTESIAN_POINT('',(2.2477766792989,4.,2.06155281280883));
#986=B_SPLINE_CURVE_WITH_KNOTS('',3,(#956,#957,#958,#959,#960,#961,#962,#963,#964,#965,#966,
#967,#968,#969,#970,#971,#972,#973,#974,#975,#976,#977,#978,#979,#980,#981,#982,#983,#984,#985),
.UNSPECIFIED.,.F.,.F.,(4,2,2,2,2,2,2,2,2,2,2,2,2,2,4),(0.,0.280295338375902,0.560756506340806,
0.843756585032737,1.12667086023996,1.58593250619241,2.04337838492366,2.42998670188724,
2.81642788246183,3.20228789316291,3.58870281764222,4.10781559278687,4.62768900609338,
4.94902769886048,5.26884492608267),.UNSPECIFIED.);
#987=EDGE_CURVE('E236',#953,#948,#986,.T.);
#988=ORIENTED_EDGE('',*,*,#987,.T.);
#989=EDGE_LOOP('',(#950,#951,#955,#988));
#990=FACE_BOUND('',#989,.T.);
#991=ADVANCED_FACE('F167',(#990),#245,.T.);
#992=CARTESIAN_POINT('',(0.,4.,0.));
#993=DIRECTION('',(0.,-1.,0.));
#994=DIRECTION('',(0.,0.,-1.));
#995=AXIS2_PLACEMENT_3D('',#992,#993,#994);
#996=PLANE('',#995);
#997=ORIENTED_EDGE('',*,*,#954,.F.);
#998=ORIENTED_EDGE('',*,*,#898,.F.);
#999=ORIENTED_EDGE('',*,*,#949,.F.);
#1000=CARTESIAN_POINT('',(0.,4.,0.));
#1001=DIRECTION('',(0.,-1.,0.));
#1002=DIRECTION('',(0.,0.,-1.));
#1003=AXIS2_PLACEMENT_3D('',#1000,#1001,#1002);
#1004=CIRCLE('',#1003,3.05);
#1005=EDGE_CURVE('E28',#948,#953,#1004,.T.);
#1006=ORIENTED_EDGE('',*,*,#1005,.T.);
#1007=EDGE_LOOP('',(#997,#998,#999,#1006));
#1008=FACE_BOUND('',#1007,.T.);
#1009=ADVANCED_FACE('F234',(#1008),#996,.T.);
#1010=ORIENTED_EDGE('',*,*,#1005,.F.);
#1011=ORIENTED_EDGE('',*,*,#987,.F.);
#1012=EDGE_LOOP('',(#1010,#1011));
#1013=FACE_BOUND('',#1012,.T.);
#1014=ADVANCED_FACE('F331',(#1013),#807,.F.);
#1015=DIRECTION('',(1.,0.,0.));
#1016=VECTOR('',#1015,1.);
#1017=CARTESIAN_POINT('',(3.9,4.,-2.06155281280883));
#1018=LINE('',#1017,#1016);
#1019=CARTESIAN_POINT('',(-2.24777667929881,4.00000000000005,-2.06155281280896));
#1020=VERTEX_POINT('',#1019);
#1021=EDGE_CURVE('E22',#1020,#910,#1018,.T.);
#1022=ORIENTED_EDGE('',*,*,#1021,.T.);
#1023=ORIENTED_EDGE('',*,*,#932,.T.);
#1024=CARTESIAN_POINT('',(2.2477766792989,4.,-2.06155281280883));
#1025=VERTEX_POINT('',#1024);
#1026=EDGE_CURVE('E104',#908,#1025,#1018,.T.);
#1027=ORIENTED_EDGE('',*,*,#1026,.T.);
#1028=CARTESIAN_POINT('',(2.2477766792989,4.,-2.06155281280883));
#1029=CARTESIAN_POINT('',(2.18870941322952,3.96682476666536,-2.12593900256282));
#1030=CARTESIAN_POINT('',(2.12705096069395,3.93305483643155,-2.18762834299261));
#1031=CARTESIAN_POINT('',(1.99874333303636,3.86516153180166,-2.30545762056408));
#1032=CARTESIAN_POINT('',(1.93209122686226,3.83103796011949,-2.36159425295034));
#1033=CARTESIAN_POINT('',(1.79343359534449,3.76300806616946,-2.46856778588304));
#1034=CARTESIAN_POINT('',(1.72138506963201,3.72910650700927,-2.51935210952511));
#1035=CARTESIAN_POINT('',(1.57269548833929,3.66284632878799,-2.61475280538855));
#1036=CARTESIAN_POINT('',(1.4960558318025,3.63048724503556,-2.65937104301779));
#1037=CARTESIAN_POINT('',(1.28908396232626,3.54899340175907,-2.76797473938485));
#1038=CARTESIAN_POINT('',(1.15506092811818,3.50197453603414,-2.82669658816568));
#1039=CARTESIAN_POINT('',(0.877003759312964,3.4204011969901,-2.9248870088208));
#1040=CARTESIAN_POINT('',(0.733011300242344,3.385798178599,-2.96443078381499));
#1041=CARTESIAN_POINT('',(0.460527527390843,3.33833884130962,-3.01771031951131));
#1042=CARTESIAN_POINT('',(0.333088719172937,3.32294472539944,-3.03449431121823));
#1043=CARTESIAN_POINT('',(0.0761818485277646,3.307100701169,-3.05176049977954));
#1044=CARTESIAN_POINT('',(-0.0532853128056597,3.30664433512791,-3.05224974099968));
#1045=CARTESIAN_POINT('',(-0.310178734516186,3.32073117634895,-3.03691226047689));
#1046=CARTESIAN_POINT('',(-0.437607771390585,3.33525182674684,-3.02111007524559));
#1047=CARTESIAN_POINT('',(-0.687505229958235,3.37711579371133,-2.97423152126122));
#1048=CARTESIAN_POINT('',(-0.809966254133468,3.40447752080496,-2.94313321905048));
#1049=CARTESIAN_POINT('',(-1.08867524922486,3.47979949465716,-2.85402192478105));
#1050=CARTESIAN_POINT('',(-1.24208423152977,3.53160669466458,-2.7904336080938));
#1051=CARTESIAN_POINT('',(-1.53407407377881,3.64453813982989,-2.64122776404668));
#1052=CARTESIAN_POINT('',(-1.67263287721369,3.70567592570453,-2.55557809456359));
#1053=CARTESIAN_POINT('',(-1.88374623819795,3.80670623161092,-2.40083120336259));
#1054=CARTESIAN_POINT('',(-1.96129972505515,3.84579576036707,-2.3379039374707));
#1055=CARTESIAN_POINT('',(-2.10958838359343,3.92351112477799,-2.20498836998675));
#1056=CARTESIAN_POINT('',(-2.180354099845,3.96213827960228,-2.13503491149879));
#1057=CARTESIAN_POINT('',(-2.2477766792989,4.,-2.06155281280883));
#1058=B_SPLINE_CURVE_WITH_KNOTS('',3,(#1028,#1029,#1030,#1031,#1032,#1033,#1034,#1035,#1036,
#1037,#1038,#1039,#1040,#1041,#1042,#1043,#1044,#1045,#1046,#1047,#1048,#1049,#1050,#1051,#1052,
#1053,#1054,#1055,#1056,#1057),.UNSPECIFIED.,.F.,.F.,(4,2,2,2,2,2,2,2,2,2,2,2,2,2,4),(0.,
0.280295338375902,0.560756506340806,0.843756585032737,1.12667086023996,1.58593250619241,
2.04337838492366,2.42998670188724,2.81642788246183,3.20228789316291,3.58870281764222,
4.10781559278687,4.62768900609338,4.94902769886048,5.26884492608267),.UNSPECIFIED.);
#1059=EDGE_CURVE('E108',#1025,#1020,#1058,.T.);
#1060=ORIENTED_EDGE('',*,*,#1059,.T.);
#1061=EDGE_LOOP('',(#1022,#1023,#1027,#1060));
#1062=FACE_BOUND('',#1061,.T.);
#1063=ADVANCED_FACE('F106',(#1062),#245,.T.);
#1064=EDGE_CURVE('E242',#1020,#1025,#1004,.T.);
#1065=ORIENTED_EDGE('',*,*,#1064,.F.);
#1066=ORIENTED_EDGE('',*,*,#1059,.F.);
#1067=EDGE_LOOP('',(#1065,#1066));
#1068=FACE_BOUND('',#1067,.T.);
#1069=ADVANCED_FACE('F330',(#1068),#807,.F.);
#1070=ORIENTED_EDGE('',*,*,#1021,.F.);
#1071=ORIENTED_EDGE('',*,*,#1064,.T.);
#1072=ORIENTED_EDGE('',*,*,#1026,.F.);
#1073=ORIENTED_EDGE('',*,*,#911,.T.);
#1074=EDGE_LOOP('',(#1070,#1071,#1072,#1073));
#1075=FACE_BOUND('',#1074,.T.);
#1076=ADVANCED_FACE('F102',(#1075),#996,.T.);
#1077=CLOSED_SHELL('',(#240,#442,#628,#660,#670,#690,#710,#730,#744,#763,#773,#789,#802,#814,
#831,#838,#853,#862,#942,#991,#1009,#1014,#1063,#1069,#1076));
#1078=MANIFOLD_SOLID_BREP('B1',#1077);
#1079=ADVANCED_BREP_SHAPE_REPRESENTATION('',(#18,#1078),#14);
#1080=SHAPE_DEFINITION_REPRESENTATION(#9,#1079);
ENDSEC;
END-ISO-10303-21;
